VERSION 5.4 ;
NAMESCASESENSITIVE ON ;
BUSBITCHARS "[]" ;
DIVIDERCHAR "/" ;
UNITS
  DATABASE MICRONS 2000 ;
END UNITS
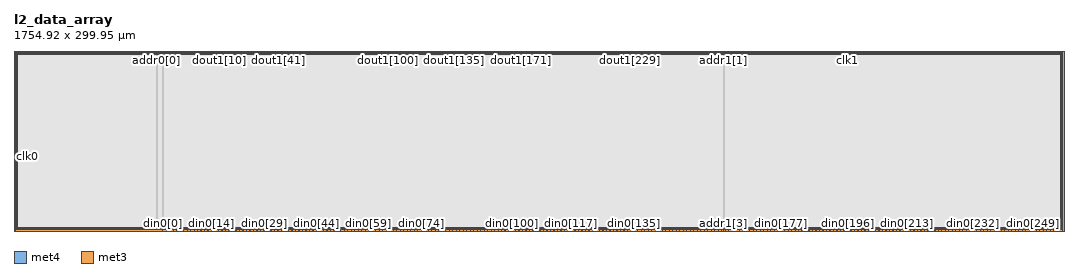
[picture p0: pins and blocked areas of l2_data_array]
MACRO l2_data_array
   CLASS BLOCK ;
   SIZE 1754.92 BY 299.95 ;
   SYMMETRY X Y R90 ;
   PIN din0[0]
      DIRECTION INPUT ;
      PORT
         LAYER met4 ;
         RECT  248.3 0.0 248.68 0.38 ;
      END
   END din0[0]
   PIN din0[1]
      DIRECTION INPUT ;
      PORT
         LAYER met4 ;
         RECT  254.14 0.0 254.52 0.38 ;
      END
   END din0[1]
   PIN din0[2]
      DIRECTION INPUT ;
      PORT
         LAYER met4 ;
         RECT  259.98 0.0 260.36 0.38 ;
      END
   END din0[2]
   PIN din0[3]
      DIRECTION INPUT ;
      PORT
         LAYER met4 ;
         RECT  265.82 0.0 266.2 0.38 ;
      END
   END din0[3]
   PIN din0[4]
      DIRECTION INPUT ;
      PORT
         LAYER met4 ;
         RECT  271.66 0.0 272.04 0.38 ;
      END
   END din0[4]
   PIN din0[5]
      DIRECTION INPUT ;
      PORT
         LAYER met4 ;
         RECT  277.5 0.0 277.88 0.38 ;
      END
   END din0[5]
   PIN din0[6]
      DIRECTION INPUT ;
      PORT
         LAYER met4 ;
         RECT  283.34 0.0 283.72 0.38 ;
      END
   END din0[6]
   PIN din0[7]
      DIRECTION INPUT ;
      PORT
         LAYER met4 ;
         RECT  289.18 0.0 289.56 0.38 ;
      END
   END din0[7]
   PIN din0[8]
      DIRECTION INPUT ;
      PORT
         LAYER met4 ;
         RECT  295.02 0.0 295.4 0.38 ;
      END
   END din0[8]
   PIN din0[9]
      DIRECTION INPUT ;
      PORT
         LAYER met4 ;
         RECT  300.86 0.0 301.24 0.38 ;
      END
   END din0[9]
   PIN din0[10]
      DIRECTION INPUT ;
      PORT
         LAYER met4 ;
         RECT  306.7 0.0 307.08 0.38 ;
      END
   END din0[10]
   PIN din0[11]
      DIRECTION INPUT ;
      PORT
         LAYER met4 ;
         RECT  312.54 0.0 312.92 0.38 ;
      END
   END din0[11]
   PIN din0[12]
      DIRECTION INPUT ;
      PORT
         LAYER met4 ;
         RECT  318.38 0.0 318.76 0.38 ;
      END
   END din0[12]
   PIN din0[13]
      DIRECTION INPUT ;
      PORT
         LAYER met4 ;
         RECT  324.22 0.0 324.6 0.38 ;
      END
   END din0[13]
   PIN din0[14]
      DIRECTION INPUT ;
      PORT
         LAYER met4 ;
         RECT  330.06 0.0 330.44 0.38 ;
      END
   END din0[14]
   PIN din0[15]
      DIRECTION INPUT ;
      PORT
         LAYER met4 ;
         RECT  335.9 0.0 336.28 0.38 ;
      END
   END din0[15]
   PIN din0[16]
      DIRECTION INPUT ;
      PORT
         LAYER met4 ;
         RECT  341.74 0.0 342.12 0.38 ;
      END
   END din0[16]
   PIN din0[17]
      DIRECTION INPUT ;
      PORT
         LAYER met4 ;
         RECT  347.58 0.0 347.96 0.38 ;
      END
   END din0[17]
   PIN din0[18]
      DIRECTION INPUT ;
      PORT
         LAYER met4 ;
         RECT  353.42 0.0 353.8 0.38 ;
      END
   END din0[18]
   PIN din0[19]
      DIRECTION INPUT ;
      PORT
         LAYER met4 ;
         RECT  359.26 0.0 359.64 0.38 ;
      END
   END din0[19]
   PIN din0[20]
      DIRECTION INPUT ;
      PORT
         LAYER met4 ;
         RECT  365.1 0.0 365.48 0.38 ;
      END
   END din0[20]
   PIN din0[21]
      DIRECTION INPUT ;
      PORT
         LAYER met4 ;
         RECT  370.94 0.0 371.32 0.38 ;
      END
   END din0[21]
   PIN din0[22]
      DIRECTION INPUT ;
      PORT
         LAYER met4 ;
         RECT  376.78 0.0 377.16 0.38 ;
      END
   END din0[22]
   PIN din0[23]
      DIRECTION INPUT ;
      PORT
         LAYER met4 ;
         RECT  382.62 0.0 383.0 0.38 ;
      END
   END din0[23]
   PIN din0[24]
      DIRECTION INPUT ;
      PORT
         LAYER met4 ;
         RECT  388.46 0.0 388.84 0.38 ;
      END
   END din0[24]
   PIN din0[25]
      DIRECTION INPUT ;
      PORT
         LAYER met4 ;
         RECT  394.3 0.0 394.68 0.38 ;
      END
   END din0[25]
   PIN din0[26]
      DIRECTION INPUT ;
      PORT
         LAYER met4 ;
         RECT  400.14 0.0 400.52 0.38 ;
      END
   END din0[26]
   PIN din0[27]
      DIRECTION INPUT ;
      PORT
         LAYER met4 ;
         RECT  405.98 0.0 406.36 0.38 ;
      END
   END din0[27]
   PIN din0[28]
      DIRECTION INPUT ;
      PORT
         LAYER met4 ;
         RECT  411.82 0.0 412.2 0.38 ;
      END
   END din0[28]
   PIN din0[29]
      DIRECTION INPUT ;
      PORT
         LAYER met4 ;
         RECT  417.66 0.0 418.04 0.38 ;
      END
   END din0[29]
   PIN din0[30]
      DIRECTION INPUT ;
      PORT
         LAYER met4 ;
         RECT  423.5 0.0 423.88 0.38 ;
      END
   END din0[30]
   PIN din0[31]
      DIRECTION INPUT ;
      PORT
         LAYER met4 ;
         RECT  429.34 0.0 429.72 0.38 ;
      END
   END din0[31]
   PIN din0[32]
      DIRECTION INPUT ;
      PORT
         LAYER met4 ;
         RECT  435.18 0.0 435.56 0.38 ;
      END
   END din0[32]
   PIN din0[33]
      DIRECTION INPUT ;
      PORT
         LAYER met4 ;
         RECT  441.02 0.0 441.4 0.38 ;
      END
   END din0[33]
   PIN din0[34]
      DIRECTION INPUT ;
      PORT
         LAYER met4 ;
         RECT  446.86 0.0 447.24 0.38 ;
      END
   END din0[34]
   PIN din0[35]
      DIRECTION INPUT ;
      PORT
         LAYER met4 ;
         RECT  452.7 0.0 453.08 0.38 ;
      END
   END din0[35]
   PIN din0[36]
      DIRECTION INPUT ;
      PORT
         LAYER met4 ;
         RECT  458.54 0.0 458.92 0.38 ;
      END
   END din0[36]
   PIN din0[37]
      DIRECTION INPUT ;
      PORT
         LAYER met4 ;
         RECT  464.38 0.0 464.76 0.38 ;
      END
   END din0[37]
   PIN din0[38]
      DIRECTION INPUT ;
      PORT
         LAYER met4 ;
         RECT  470.22 0.0 470.6 0.38 ;
      END
   END din0[38]
   PIN din0[39]
      DIRECTION INPUT ;
      PORT
         LAYER met4 ;
         RECT  476.06 0.0 476.44 0.38 ;
      END
   END din0[39]
   PIN din0[40]
      DIRECTION INPUT ;
      PORT
         LAYER met4 ;
         RECT  481.9 0.0 482.28 0.38 ;
      END
   END din0[40]
   PIN din0[41]
      DIRECTION INPUT ;
      PORT
         LAYER met4 ;
         RECT  487.74 0.0 488.12 0.38 ;
      END
   END din0[41]
   PIN din0[42]
      DIRECTION INPUT ;
      PORT
         LAYER met4 ;
         RECT  493.58 0.0 493.96 0.38 ;
      END
   END din0[42]
   PIN din0[43]
      DIRECTION INPUT ;
      PORT
         LAYER met4 ;
         RECT  499.42 0.0 499.8 0.38 ;
      END
   END din0[43]
   PIN din0[44]
      DIRECTION INPUT ;
      PORT
         LAYER met4 ;
         RECT  505.26 0.0 505.64 0.38 ;
      END
   END din0[44]
   PIN din0[45]
      DIRECTION INPUT ;
      PORT
         LAYER met4 ;
         RECT  511.1 0.0 511.48 0.38 ;
      END
   END din0[45]
   PIN din0[46]
      DIRECTION INPUT ;
      PORT
         LAYER met4 ;
         RECT  516.94 0.0 517.32 0.38 ;
      END
   END din0[46]
   PIN din0[47]
      DIRECTION INPUT ;
      PORT
         LAYER met4 ;
         RECT  522.78 0.0 523.16 0.38 ;
      END
   END din0[47]
   PIN din0[48]
      DIRECTION INPUT ;
      PORT
         LAYER met4 ;
         RECT  528.62 0.0 529.0 0.38 ;
      END
   END din0[48]
   PIN din0[49]
      DIRECTION INPUT ;
      PORT
         LAYER met4 ;
         RECT  534.46 0.0 534.84 0.38 ;
      END
   END din0[49]
   PIN din0[50]
      DIRECTION INPUT ;
      PORT
         LAYER met4 ;
         RECT  540.3 0.0 540.68 0.38 ;
      END
   END din0[50]
   PIN din0[51]
      DIRECTION INPUT ;
      PORT
         LAYER met4 ;
         RECT  546.14 0.0 546.52 0.38 ;
      END
   END din0[51]
   PIN din0[52]
      DIRECTION INPUT ;
      PORT
         LAYER met4 ;
         RECT  551.98 0.0 552.36 0.38 ;
      END
   END din0[52]
   PIN din0[53]
      DIRECTION INPUT ;
      PORT
         LAYER met4 ;
         RECT  557.82 0.0 558.2 0.38 ;
      END
   END din0[53]
   PIN din0[54]
      DIRECTION INPUT ;
      PORT
         LAYER met4 ;
         RECT  563.66 0.0 564.04 0.38 ;
      END
   END din0[54]
   PIN din0[55]
      DIRECTION INPUT ;
      PORT
         LAYER met4 ;
         RECT  569.5 0.0 569.88 0.38 ;
      END
   END din0[55]
   PIN din0[56]
      DIRECTION INPUT ;
      PORT
         LAYER met4 ;
         RECT  575.34 0.0 575.72 0.38 ;
      END
   END din0[56]
   PIN din0[57]
      DIRECTION INPUT ;
      PORT
         LAYER met4 ;
         RECT  581.18 0.0 581.56 0.38 ;
      END
   END din0[57]
   PIN din0[58]
      DIRECTION INPUT ;
      PORT
         LAYER met4 ;
         RECT  587.02 0.0 587.4 0.38 ;
      END
   END din0[58]
   PIN din0[59]
      DIRECTION INPUT ;
      PORT
         LAYER met4 ;
         RECT  592.86 0.0 593.24 0.38 ;
      END
   END din0[59]
   PIN din0[60]
      DIRECTION INPUT ;
      PORT
         LAYER met4 ;
         RECT  598.7 0.0 599.08 0.38 ;
      END
   END din0[60]
   PIN din0[61]
      DIRECTION INPUT ;
      PORT
         LAYER met4 ;
         RECT  604.54 0.0 604.92 0.38 ;
      END
   END din0[61]
   PIN din0[62]
      DIRECTION INPUT ;
      PORT
         LAYER met4 ;
         RECT  610.38 0.0 610.76 0.38 ;
      END
   END din0[62]
   PIN din0[63]
      DIRECTION INPUT ;
      PORT
         LAYER met4 ;
         RECT  616.22 0.0 616.6 0.38 ;
      END
   END din0[63]
   PIN din0[64]
      DIRECTION INPUT ;
      PORT
         LAYER met4 ;
         RECT  622.06 0.0 622.44 0.38 ;
      END
   END din0[64]
   PIN din0[65]
      DIRECTION INPUT ;
      PORT
         LAYER met4 ;
         RECT  627.9 0.0 628.28 0.38 ;
      END
   END din0[65]
   PIN din0[66]
      DIRECTION INPUT ;
      PORT
         LAYER met4 ;
         RECT  633.74 0.0 634.12 0.38 ;
      END
   END din0[66]
   PIN din0[67]
      DIRECTION INPUT ;
      PORT
         LAYER met4 ;
         RECT  639.58 0.0 639.96 0.38 ;
      END
   END din0[67]
   PIN din0[68]
      DIRECTION INPUT ;
      PORT
         LAYER met4 ;
         RECT  645.42 0.0 645.8 0.38 ;
      END
   END din0[68]
   PIN din0[69]
      DIRECTION INPUT ;
      PORT
         LAYER met4 ;
         RECT  651.26 0.0 651.64 0.38 ;
      END
   END din0[69]
   PIN din0[70]
      DIRECTION INPUT ;
      PORT
         LAYER met4 ;
         RECT  657.1 0.0 657.48 0.38 ;
      END
   END din0[70]
   PIN din0[71]
      DIRECTION INPUT ;
      PORT
         LAYER met4 ;
         RECT  662.94 0.0 663.32 0.38 ;
      END
   END din0[71]
   PIN din0[72]
      DIRECTION INPUT ;
      PORT
         LAYER met4 ;
         RECT  668.78 0.0 669.16 0.38 ;
      END
   END din0[72]
   PIN din0[73]
      DIRECTION INPUT ;
      PORT
         LAYER met4 ;
         RECT  674.62 0.0 675.0 0.38 ;
      END
   END din0[73]
   PIN din0[74]
      DIRECTION INPUT ;
      PORT
         LAYER met4 ;
         RECT  680.46 0.0 680.84 0.38 ;
      END
   END din0[74]
   PIN din0[75]
      DIRECTION INPUT ;
      PORT
         LAYER met4 ;
         RECT  686.3 0.0 686.68 0.38 ;
      END
   END din0[75]
   PIN din0[76]
      DIRECTION INPUT ;
      PORT
         LAYER met4 ;
         RECT  692.14 0.0 692.52 0.38 ;
      END
   END din0[76]
   PIN din0[77]
      DIRECTION INPUT ;
      PORT
         LAYER met4 ;
         RECT  697.98 0.0 698.36 0.38 ;
      END
   END din0[77]
   PIN din0[78]
      DIRECTION INPUT ;
      PORT
         LAYER met4 ;
         RECT  703.82 0.0 704.2 0.38 ;
      END
   END din0[78]
   PIN din0[79]
      DIRECTION INPUT ;
      PORT
         LAYER met4 ;
         RECT  709.66 0.0 710.04 0.38 ;
      END
   END din0[79]
   PIN din0[80]
      DIRECTION INPUT ;
      PORT
         LAYER met4 ;
         RECT  715.5 0.0 715.88 0.38 ;
      END
   END din0[80]
   PIN din0[81]
      DIRECTION INPUT ;
      PORT
         LAYER met4 ;
         RECT  721.34 0.0 721.72 0.38 ;
      END
   END din0[81]
   PIN din0[82]
      DIRECTION INPUT ;
      PORT
         LAYER met4 ;
         RECT  727.18 0.0 727.56 0.38 ;
      END
   END din0[82]
   PIN din0[83]
      DIRECTION INPUT ;
      PORT
         LAYER met4 ;
         RECT  733.02 0.0 733.4 0.38 ;
      END
   END din0[83]
   PIN din0[84]
      DIRECTION INPUT ;
      PORT
         LAYER met4 ;
         RECT  738.86 0.0 739.24 0.38 ;
      END
   END din0[84]
   PIN din0[85]
      DIRECTION INPUT ;
      PORT
         LAYER met4 ;
         RECT  744.7 0.0 745.08 0.38 ;
      END
   END din0[85]
   PIN din0[86]
      DIRECTION INPUT ;
      PORT
         LAYER met4 ;
         RECT  750.54 0.0 750.92 0.38 ;
      END
   END din0[86]
   PIN din0[87]
      DIRECTION INPUT ;
      PORT
         LAYER met4 ;
         RECT  756.38 0.0 756.76 0.38 ;
      END
   END din0[87]
   PIN din0[88]
      DIRECTION INPUT ;
      PORT
         LAYER met4 ;
         RECT  762.22 0.0 762.6 0.38 ;
      END
   END din0[88]
   PIN din0[89]
      DIRECTION INPUT ;
      PORT
         LAYER met4 ;
         RECT  768.06 0.0 768.44 0.38 ;
      END
   END din0[89]
   PIN din0[90]
      DIRECTION INPUT ;
      PORT
         LAYER met4 ;
         RECT  773.9 0.0 774.28 0.38 ;
      END
   END din0[90]
   PIN din0[91]
      DIRECTION INPUT ;
      PORT
         LAYER met4 ;
         RECT  779.74 0.0 780.12 0.38 ;
      END
   END din0[91]
   PIN din0[92]
      DIRECTION INPUT ;
      PORT
         LAYER met4 ;
         RECT  785.58 0.0 785.96 0.38 ;
      END
   END din0[92]
   PIN din0[93]
      DIRECTION INPUT ;
      PORT
         LAYER met4 ;
         RECT  791.42 0.0 791.8 0.38 ;
      END
   END din0[93]
   PIN din0[94]
      DIRECTION INPUT ;
      PORT
         LAYER met4 ;
         RECT  797.26 0.0 797.64 0.38 ;
      END
   END din0[94]
   PIN din0[95]
      DIRECTION INPUT ;
      PORT
         LAYER met4 ;
         RECT  803.1 0.0 803.48 0.38 ;
      END
   END din0[95]
   PIN din0[96]
      DIRECTION INPUT ;
      PORT
         LAYER met4 ;
         RECT  808.94 0.0 809.32 0.38 ;
      END
   END din0[96]
   PIN din0[97]
      DIRECTION INPUT ;
      PORT
         LAYER met4 ;
         RECT  814.78 0.0 815.16 0.38 ;
      END
   END din0[97]
   PIN din0[98]
      DIRECTION INPUT ;
      PORT
         LAYER met4 ;
         RECT  820.62 0.0 821.0 0.38 ;
      END
   END din0[98]
   PIN din0[99]
      DIRECTION INPUT ;
      PORT
         LAYER met4 ;
         RECT  826.46 0.0 826.84 0.38 ;
      END
   END din0[99]
   PIN din0[100]
      DIRECTION INPUT ;
      PORT
         LAYER met4 ;
         RECT  832.3 0.0 832.68 0.38 ;
      END
   END din0[100]
   PIN din0[101]
      DIRECTION INPUT ;
      PORT
         LAYER met4 ;
         RECT  838.14 0.0 838.52 0.38 ;
      END
   END din0[101]
   PIN din0[102]
      DIRECTION INPUT ;
      PORT
         LAYER met4 ;
         RECT  843.98 0.0 844.36 0.38 ;
      END
   END din0[102]
   PIN din0[103]
      DIRECTION INPUT ;
      PORT
         LAYER met4 ;
         RECT  849.82 0.0 850.2 0.38 ;
      END
   END din0[103]
   PIN din0[104]
      DIRECTION INPUT ;
      PORT
         LAYER met4 ;
         RECT  855.66 0.0 856.04 0.38 ;
      END
   END din0[104]
   PIN din0[105]
      DIRECTION INPUT ;
      PORT
         LAYER met4 ;
         RECT  861.5 0.0 861.88 0.38 ;
      END
   END din0[105]
   PIN din0[106]
      DIRECTION INPUT ;
      PORT
         LAYER met4 ;
         RECT  867.34 0.0 867.72 0.38 ;
      END
   END din0[106]
   PIN din0[107]
      DIRECTION INPUT ;
      PORT
         LAYER met4 ;
         RECT  873.18 0.0 873.56 0.38 ;
      END
   END din0[107]
   PIN din0[108]
      DIRECTION INPUT ;
      PORT
         LAYER met4 ;
         RECT  879.02 0.0 879.4 0.38 ;
      END
   END din0[108]
   PIN din0[109]
      DIRECTION INPUT ;
      PORT
         LAYER met4 ;
         RECT  884.86 0.0 885.24 0.38 ;
      END
   END din0[109]
   PIN din0[110]
      DIRECTION INPUT ;
      PORT
         LAYER met4 ;
         RECT  890.7 0.0 891.08 0.38 ;
      END
   END din0[110]
   PIN din0[111]
      DIRECTION INPUT ;
      PORT
         LAYER met4 ;
         RECT  896.54 0.0 896.92 0.38 ;
      END
   END din0[111]
   PIN din0[112]
      DIRECTION INPUT ;
      PORT
         LAYER met4 ;
         RECT  902.38 0.0 902.76 0.38 ;
      END
   END din0[112]
   PIN din0[113]
      DIRECTION INPUT ;
      PORT
         LAYER met4 ;
         RECT  908.22 0.0 908.6 0.38 ;
      END
   END din0[113]
   PIN din0[114]
      DIRECTION INPUT ;
      PORT
         LAYER met4 ;
         RECT  914.06 0.0 914.44 0.38 ;
      END
   END din0[114]
   PIN din0[115]
      DIRECTION INPUT ;
      PORT
         LAYER met4 ;
         RECT  919.9 0.0 920.28 0.38 ;
      END
   END din0[115]
   PIN din0[116]
      DIRECTION INPUT ;
      PORT
         LAYER met4 ;
         RECT  925.74 0.0 926.12 0.38 ;
      END
   END din0[116]
   PIN din0[117]
      DIRECTION INPUT ;
      PORT
         LAYER met4 ;
         RECT  931.58 0.0 931.96 0.38 ;
      END
   END din0[117]
   PIN din0[118]
      DIRECTION INPUT ;
      PORT
         LAYER met4 ;
         RECT  937.42 0.0 937.8 0.38 ;
      END
   END din0[118]
   PIN din0[119]
      DIRECTION INPUT ;
      PORT
         LAYER met4 ;
         RECT  943.26 0.0 943.64 0.38 ;
      END
   END din0[119]
   PIN din0[120]
      DIRECTION INPUT ;
      PORT
         LAYER met4 ;
         RECT  949.1 0.0 949.48 0.38 ;
      END
   END din0[120]
   PIN din0[121]
      DIRECTION INPUT ;
      PORT
         LAYER met4 ;
         RECT  954.94 0.0 955.32 0.38 ;
      END
   END din0[121]
   PIN din0[122]
      DIRECTION INPUT ;
      PORT
         LAYER met4 ;
         RECT  960.78 0.0 961.16 0.38 ;
      END
   END din0[122]
   PIN din0[123]
      DIRECTION INPUT ;
      PORT
         LAYER met4 ;
         RECT  966.62 0.0 967.0 0.38 ;
      END
   END din0[123]
   PIN din0[124]
      DIRECTION INPUT ;
      PORT
         LAYER met4 ;
         RECT  972.46 0.0 972.84 0.38 ;
      END
   END din0[124]
   PIN din0[125]
      DIRECTION INPUT ;
      PORT
         LAYER met4 ;
         RECT  978.3 0.0 978.68 0.38 ;
      END
   END din0[125]
   PIN din0[126]
      DIRECTION INPUT ;
      PORT
         LAYER met4 ;
         RECT  984.14 0.0 984.52 0.38 ;
      END
   END din0[126]
   PIN din0[127]
      DIRECTION INPUT ;
      PORT
         LAYER met4 ;
         RECT  989.98 0.0 990.36 0.38 ;
      END
   END din0[127]
   PIN din0[128]
      DIRECTION INPUT ;
      PORT
         LAYER met4 ;
         RECT  995.82 0.0 996.2 0.38 ;
      END
   END din0[128]
   PIN din0[129]
      DIRECTION INPUT ;
      PORT
         LAYER met4 ;
         RECT  1001.66 0.0 1002.04 0.38 ;
      END
   END din0[129]
   PIN din0[130]
      DIRECTION INPUT ;
      PORT
         LAYER met4 ;
         RECT  1007.5 0.0 1007.88 0.38 ;
      END
   END din0[130]
   PIN din0[131]
      DIRECTION INPUT ;
      PORT
         LAYER met4 ;
         RECT  1013.34 0.0 1013.72 0.38 ;
      END
   END din0[131]
   PIN din0[132]
      DIRECTION INPUT ;
      PORT
         LAYER met4 ;
         RECT  1019.18 0.0 1019.56 0.38 ;
      END
   END din0[132]
   PIN din0[133]
      DIRECTION INPUT ;
      PORT
         LAYER met4 ;
         RECT  1025.02 0.0 1025.4 0.38 ;
      END
   END din0[133]
   PIN din0[134]
      DIRECTION INPUT ;
      PORT
         LAYER met4 ;
         RECT  1030.86 0.0 1031.24 0.38 ;
      END
   END din0[134]
   PIN din0[135]
      DIRECTION INPUT ;
      PORT
         LAYER met4 ;
         RECT  1036.7 0.0 1037.08 0.38 ;
      END
   END din0[135]
   PIN din0[136]
      DIRECTION INPUT ;
      PORT
         LAYER met4 ;
         RECT  1042.54 0.0 1042.92 0.38 ;
      END
   END din0[136]
   PIN din0[137]
      DIRECTION INPUT ;
      PORT
         LAYER met4 ;
         RECT  1048.38 0.0 1048.76 0.38 ;
      END
   END din0[137]
   PIN din0[138]
      DIRECTION INPUT ;
      PORT
         LAYER met4 ;
         RECT  1054.22 0.0 1054.6 0.38 ;
      END
   END din0[138]
   PIN din0[139]
      DIRECTION INPUT ;
      PORT
         LAYER met4 ;
         RECT  1060.06 0.0 1060.44 0.38 ;
      END
   END din0[139]
   PIN din0[140]
      DIRECTION INPUT ;
      PORT
         LAYER met4 ;
         RECT  1065.9 0.0 1066.28 0.38 ;
      END
   END din0[140]
   PIN din0[141]
      DIRECTION INPUT ;
      PORT
         LAYER met4 ;
         RECT  1071.74 0.0 1072.12 0.38 ;
      END
   END din0[141]
   PIN din0[142]
      DIRECTION INPUT ;
      PORT
         LAYER met4 ;
         RECT  1077.58 0.0 1077.96 0.38 ;
      END
   END din0[142]
   PIN din0[143]
      DIRECTION INPUT ;
      PORT
         LAYER met4 ;
         RECT  1083.42 0.0 1083.8 0.38 ;
      END
   END din0[143]
   PIN din0[144]
      DIRECTION INPUT ;
      PORT
         LAYER met4 ;
         RECT  1089.26 0.0 1089.64 0.38 ;
      END
   END din0[144]
   PIN din0[145]
      DIRECTION INPUT ;
      PORT
         LAYER met4 ;
         RECT  1095.1 0.0 1095.48 0.38 ;
      END
   END din0[145]
   PIN din0[146]
      DIRECTION INPUT ;
      PORT
         LAYER met4 ;
         RECT  1100.94 0.0 1101.32 0.38 ;
      END
   END din0[146]
   PIN din0[147]
      DIRECTION INPUT ;
      PORT
         LAYER met4 ;
         RECT  1106.78 0.0 1107.16 0.38 ;
      END
   END din0[147]
   PIN din0[148]
      DIRECTION INPUT ;
      PORT
         LAYER met4 ;
         RECT  1112.62 0.0 1113.0 0.38 ;
      END
   END din0[148]
   PIN din0[149]
      DIRECTION INPUT ;
      PORT
         LAYER met4 ;
         RECT  1118.46 0.0 1118.84 0.38 ;
      END
   END din0[149]
   PIN din0[150]
      DIRECTION INPUT ;
      PORT
         LAYER met4 ;
         RECT  1124.3 0.0 1124.68 0.38 ;
      END
   END din0[150]
   PIN din0[151]
      DIRECTION INPUT ;
      PORT
         LAYER met4 ;
         RECT  1130.14 0.0 1130.52 0.38 ;
      END
   END din0[151]
   PIN din0[152]
      DIRECTION INPUT ;
      PORT
         LAYER met4 ;
         RECT  1135.98 0.0 1136.36 0.38 ;
      END
   END din0[152]
   PIN din0[153]
      DIRECTION INPUT ;
      PORT
         LAYER met4 ;
         RECT  1141.82 0.0 1142.2 0.38 ;
      END
   END din0[153]
   PIN din0[154]
      DIRECTION INPUT ;
      PORT
         LAYER met4 ;
         RECT  1147.66 0.0 1148.04 0.38 ;
      END
   END din0[154]
   PIN din0[155]
      DIRECTION INPUT ;
      PORT
         LAYER met4 ;
         RECT  1153.5 0.0 1153.88 0.38 ;
      END
   END din0[155]
   PIN din0[156]
      DIRECTION INPUT ;
      PORT
         LAYER met4 ;
         RECT  1159.34 0.0 1159.72 0.38 ;
      END
   END din0[156]
   PIN din0[157]
      DIRECTION INPUT ;
      PORT
         LAYER met4 ;
         RECT  1165.18 0.0 1165.56 0.38 ;
      END
   END din0[157]
   PIN din0[158]
      DIRECTION INPUT ;
      PORT
         LAYER met4 ;
         RECT  1171.02 0.0 1171.4 0.38 ;
      END
   END din0[158]
   PIN din0[159]
      DIRECTION INPUT ;
      PORT
         LAYER met4 ;
         RECT  1176.86 0.0 1177.24 0.38 ;
      END
   END din0[159]
   PIN din0[160]
      DIRECTION INPUT ;
      PORT
         LAYER met4 ;
         RECT  1182.7 0.0 1183.08 0.38 ;
      END
   END din0[160]
   PIN din0[161]
      DIRECTION INPUT ;
      PORT
         LAYER met4 ;
         RECT  1188.54 0.0 1188.92 0.38 ;
      END
   END din0[161]
   PIN din0[162]
      DIRECTION INPUT ;
      PORT
         LAYER met4 ;
         RECT  1194.38 0.0 1194.76 0.38 ;
      END
   END din0[162]
   PIN din0[163]
      DIRECTION INPUT ;
      PORT
         LAYER met4 ;
         RECT  1200.22 0.0 1200.6 0.38 ;
      END
   END din0[163]
   PIN din0[164]
      DIRECTION INPUT ;
      PORT
         LAYER met4 ;
         RECT  1206.06 0.0 1206.44 0.38 ;
      END
   END din0[164]
   PIN din0[165]
      DIRECTION INPUT ;
      PORT
         LAYER met4 ;
         RECT  1211.9 0.0 1212.28 0.38 ;
      END
   END din0[165]
   PIN din0[166]
      DIRECTION INPUT ;
      PORT
         LAYER met4 ;
         RECT  1217.74 0.0 1218.12 0.38 ;
      END
   END din0[166]
   PIN din0[167]
      DIRECTION INPUT ;
      PORT
         LAYER met4 ;
         RECT  1223.58 0.0 1223.96 0.38 ;
      END
   END din0[167]
   PIN din0[168]
      DIRECTION INPUT ;
      PORT
         LAYER met4 ;
         RECT  1229.42 0.0 1229.8 0.38 ;
      END
   END din0[168]
   PIN din0[169]
      DIRECTION INPUT ;
      PORT
         LAYER met4 ;
         RECT  1235.26 0.0 1235.64 0.38 ;
      END
   END din0[169]
   PIN din0[170]
      DIRECTION INPUT ;
      PORT
         LAYER met4 ;
         RECT  1241.1 0.0 1241.48 0.38 ;
      END
   END din0[170]
   PIN din0[171]
      DIRECTION INPUT ;
      PORT
         LAYER met4 ;
         RECT  1246.94 0.0 1247.32 0.38 ;
      END
   END din0[171]
   PIN din0[172]
      DIRECTION INPUT ;
      PORT
         LAYER met4 ;
         RECT  1252.78 0.0 1253.16 0.38 ;
      END
   END din0[172]
   PIN din0[173]
      DIRECTION INPUT ;
      PORT
         LAYER met4 ;
         RECT  1258.62 0.0 1259.0 0.38 ;
      END
   END din0[173]
   PIN din0[174]
      DIRECTION INPUT ;
      PORT
         LAYER met4 ;
         RECT  1264.46 0.0 1264.84 0.38 ;
      END
   END din0[174]
   PIN din0[175]
      DIRECTION INPUT ;
      PORT
         LAYER met4 ;
         RECT  1270.3 0.0 1270.68 0.38 ;
      END
   END din0[175]
   PIN din0[176]
      DIRECTION INPUT ;
      PORT
         LAYER met4 ;
         RECT  1276.14 0.0 1276.52 0.38 ;
      END
   END din0[176]
   PIN din0[177]
      DIRECTION INPUT ;
      PORT
         LAYER met4 ;
         RECT  1281.98 0.0 1282.36 0.38 ;
      END
   END din0[177]
   PIN din0[178]
      DIRECTION INPUT ;
      PORT
         LAYER met4 ;
         RECT  1287.82 0.0 1288.2 0.38 ;
      END
   END din0[178]
   PIN din0[179]
      DIRECTION INPUT ;
      PORT
         LAYER met4 ;
         RECT  1293.66 0.0 1294.04 0.38 ;
      END
   END din0[179]
   PIN din0[180]
      DIRECTION INPUT ;
      PORT
         LAYER met4 ;
         RECT  1299.5 0.0 1299.88 0.38 ;
      END
   END din0[180]
   PIN din0[181]
      DIRECTION INPUT ;
      PORT
         LAYER met4 ;
         RECT  1305.34 0.0 1305.72 0.38 ;
      END
   END din0[181]
   PIN din0[182]
      DIRECTION INPUT ;
      PORT
         LAYER met4 ;
         RECT  1311.18 0.0 1311.56 0.38 ;
      END
   END din0[182]
   PIN din0[183]
      DIRECTION INPUT ;
      PORT
         LAYER met4 ;
         RECT  1317.02 0.0 1317.4 0.38 ;
      END
   END din0[183]
   PIN din0[184]
      DIRECTION INPUT ;
      PORT
         LAYER met4 ;
         RECT  1322.86 0.0 1323.24 0.38 ;
      END
   END din0[184]
   PIN din0[185]
      DIRECTION INPUT ;
      PORT
         LAYER met4 ;
         RECT  1328.7 0.0 1329.08 0.38 ;
      END
   END din0[185]
   PIN din0[186]
      DIRECTION INPUT ;
      PORT
         LAYER met4 ;
         RECT  1334.54 0.0 1334.92 0.38 ;
      END
   END din0[186]
   PIN din0[187]
      DIRECTION INPUT ;
      PORT
         LAYER met4 ;
         RECT  1340.38 0.0 1340.76 0.38 ;
      END
   END din0[187]
   PIN din0[188]
      DIRECTION INPUT ;
      PORT
         LAYER met4 ;
         RECT  1346.22 0.0 1346.6 0.38 ;
      END
   END din0[188]
   PIN din0[189]
      DIRECTION INPUT ;
      PORT
         LAYER met4 ;
         RECT  1352.06 0.0 1352.44 0.38 ;
      END
   END din0[189]
   PIN din0[190]
      DIRECTION INPUT ;
      PORT
         LAYER met4 ;
         RECT  1357.9 0.0 1358.28 0.38 ;
      END
   END din0[190]
   PIN din0[191]
      DIRECTION INPUT ;
      PORT
         LAYER met4 ;
         RECT  1363.74 0.0 1364.12 0.38 ;
      END
   END din0[191]
   PIN din0[192]
      DIRECTION INPUT ;
      PORT
         LAYER met4 ;
         RECT  1369.58 0.0 1369.96 0.38 ;
      END
   END din0[192]
   PIN din0[193]
      DIRECTION INPUT ;
      PORT
         LAYER met4 ;
         RECT  1375.42 0.0 1375.8 0.38 ;
      END
   END din0[193]
   PIN din0[194]
      DIRECTION INPUT ;
      PORT
         LAYER met4 ;
         RECT  1381.26 0.0 1381.64 0.38 ;
      END
   END din0[194]
   PIN din0[195]
      DIRECTION INPUT ;
      PORT
         LAYER met4 ;
         RECT  1387.1 0.0 1387.48 0.38 ;
      END
   END din0[195]
   PIN din0[196]
      DIRECTION INPUT ;
      PORT
         LAYER met4 ;
         RECT  1392.94 0.0 1393.32 0.38 ;
      END
   END din0[196]
   PIN din0[197]
      DIRECTION INPUT ;
      PORT
         LAYER met4 ;
         RECT  1398.78 0.0 1399.16 0.38 ;
      END
   END din0[197]
   PIN din0[198]
      DIRECTION INPUT ;
      PORT
         LAYER met4 ;
         RECT  1404.62 0.0 1405.0 0.38 ;
      END
   END din0[198]
   PIN din0[199]
      DIRECTION INPUT ;
      PORT
         LAYER met4 ;
         RECT  1410.46 0.0 1410.84 0.38 ;
      END
   END din0[199]
   PIN din0[200]
      DIRECTION INPUT ;
      PORT
         LAYER met4 ;
         RECT  1416.3 0.0 1416.68 0.38 ;
      END
   END din0[200]
   PIN din0[201]
      DIRECTION INPUT ;
      PORT
         LAYER met4 ;
         RECT  1422.14 0.0 1422.52 0.38 ;
      END
   END din0[201]
   PIN din0[202]
      DIRECTION INPUT ;
      PORT
         LAYER met4 ;
         RECT  1427.98 0.0 1428.36 0.38 ;
      END
   END din0[202]
   PIN din0[203]
      DIRECTION INPUT ;
      PORT
         LAYER met4 ;
         RECT  1433.82 0.0 1434.2 0.38 ;
      END
   END din0[203]
   PIN din0[204]
      DIRECTION INPUT ;
      PORT
         LAYER met4 ;
         RECT  1439.66 0.0 1440.04 0.38 ;
      END
   END din0[204]
   PIN din0[205]
      DIRECTION INPUT ;
      PORT
         LAYER met4 ;
         RECT  1445.5 0.0 1445.88 0.38 ;
      END
   END din0[205]
   PIN din0[206]
      DIRECTION INPUT ;
      PORT
         LAYER met4 ;
         RECT  1451.34 0.0 1451.72 0.38 ;
      END
   END din0[206]
   PIN din0[207]
      DIRECTION INPUT ;
      PORT
         LAYER met4 ;
         RECT  1457.18 0.0 1457.56 0.38 ;
      END
   END din0[207]
   PIN din0[208]
      DIRECTION INPUT ;
      PORT
         LAYER met4 ;
         RECT  1463.02 0.0 1463.4 0.38 ;
      END
   END din0[208]
   PIN din0[209]
      DIRECTION INPUT ;
      PORT
         LAYER met4 ;
         RECT  1468.86 0.0 1469.24 0.38 ;
      END
   END din0[209]
   PIN din0[210]
      DIRECTION INPUT ;
      PORT
         LAYER met4 ;
         RECT  1474.7 0.0 1475.08 0.38 ;
      END
   END din0[210]
   PIN din0[211]
      DIRECTION INPUT ;
      PORT
         LAYER met4 ;
         RECT  1480.54 0.0 1480.92 0.38 ;
      END
   END din0[211]
   PIN din0[212]
      DIRECTION INPUT ;
      PORT
         LAYER met4 ;
         RECT  1486.38 0.0 1486.76 0.38 ;
      END
   END din0[212]
   PIN din0[213]
      DIRECTION INPUT ;
      PORT
         LAYER met4 ;
         RECT  1492.22 0.0 1492.6 0.38 ;
      END
   END din0[213]
   PIN din0[214]
      DIRECTION INPUT ;
      PORT
         LAYER met4 ;
         RECT  1498.06 0.0 1498.44 0.38 ;
      END
   END din0[214]
   PIN din0[215]
      DIRECTION INPUT ;
      PORT
         LAYER met4 ;
         RECT  1503.9 0.0 1504.28 0.38 ;
      END
   END din0[215]
   PIN din0[216]
      DIRECTION INPUT ;
      PORT
         LAYER met4 ;
         RECT  1509.74 0.0 1510.12 0.38 ;
      END
   END din0[216]
   PIN din0[217]
      DIRECTION INPUT ;
      PORT
         LAYER met4 ;
         RECT  1515.58 0.0 1515.96 0.38 ;
      END
   END din0[217]
   PIN din0[218]
      DIRECTION INPUT ;
      PORT
         LAYER met4 ;
         RECT  1521.42 0.0 1521.8 0.38 ;
      END
   END din0[218]
   PIN din0[219]
      DIRECTION INPUT ;
      PORT
         LAYER met4 ;
         RECT  1527.26 0.0 1527.64 0.38 ;
      END
   END din0[219]
   PIN din0[220]
      DIRECTION INPUT ;
      PORT
         LAYER met4 ;
         RECT  1533.1 0.0 1533.48 0.38 ;
      END
   END din0[220]
   PIN din0[221]
      DIRECTION INPUT ;
      PORT
         LAYER met4 ;
         RECT  1538.94 0.0 1539.32 0.38 ;
      END
   END din0[221]
   PIN din0[222]
      DIRECTION INPUT ;
      PORT
         LAYER met4 ;
         RECT  1544.78 0.0 1545.16 0.38 ;
      END
   END din0[222]
   PIN din0[223]
      DIRECTION INPUT ;
      PORT
         LAYER met4 ;
         RECT  1550.62 0.0 1551.0 0.38 ;
      END
   END din0[223]
   PIN din0[224]
      DIRECTION INPUT ;
      PORT
         LAYER met4 ;
         RECT  1556.46 0.0 1556.84 0.38 ;
      END
   END din0[224]
   PIN din0[225]
      DIRECTION INPUT ;
      PORT
         LAYER met4 ;
         RECT  1562.3 0.0 1562.68 0.38 ;
      END
   END din0[225]
   PIN din0[226]
      DIRECTION INPUT ;
      PORT
         LAYER met4 ;
         RECT  1568.14 0.0 1568.52 0.38 ;
      END
   END din0[226]
   PIN din0[227]
      DIRECTION INPUT ;
      PORT
         LAYER met4 ;
         RECT  1573.98 0.0 1574.36 0.38 ;
      END
   END din0[227]
   PIN din0[228]
      DIRECTION INPUT ;
      PORT
         LAYER met4 ;
         RECT  1579.82 0.0 1580.2 0.38 ;
      END
   END din0[228]
   PIN din0[229]
      DIRECTION INPUT ;
      PORT
         LAYER met4 ;
         RECT  1585.66 0.0 1586.04 0.38 ;
      END
   END din0[229]
   PIN din0[230]
      DIRECTION INPUT ;
      PORT
         LAYER met4 ;
         RECT  1591.5 0.0 1591.88 0.38 ;
      END
   END din0[230]
   PIN din0[231]
      DIRECTION INPUT ;
      PORT
         LAYER met4 ;
         RECT  1597.34 0.0 1597.72 0.38 ;
      END
   END din0[231]
   PIN din0[232]
      DIRECTION INPUT ;
      PORT
         LAYER met4 ;
         RECT  1603.18 0.0 1603.56 0.38 ;
      END
   END din0[232]
   PIN din0[233]
      DIRECTION INPUT ;
      PORT
         LAYER met4 ;
         RECT  1609.02 0.0 1609.4 0.38 ;
      END
   END din0[233]
   PIN din0[234]
      DIRECTION INPUT ;
      PORT
         LAYER met4 ;
         RECT  1614.86 0.0 1615.24 0.38 ;
      END
   END din0[234]
   PIN din0[235]
      DIRECTION INPUT ;
      PORT
         LAYER met4 ;
         RECT  1620.7 0.0 1621.08 0.38 ;
      END
   END din0[235]
   PIN din0[236]
      DIRECTION INPUT ;
      PORT
         LAYER met4 ;
         RECT  1626.54 0.0 1626.92 0.38 ;
      END
   END din0[236]
   PIN din0[237]
      DIRECTION INPUT ;
      PORT
         LAYER met4 ;
         RECT  1632.38 0.0 1632.76 0.38 ;
      END
   END din0[237]
   PIN din0[238]
      DIRECTION INPUT ;
      PORT
         LAYER met4 ;
         RECT  1638.22 0.0 1638.6 0.38 ;
      END
   END din0[238]
   PIN din0[239]
      DIRECTION INPUT ;
      PORT
         LAYER met4 ;
         RECT  1644.06 0.0 1644.44 0.38 ;
      END
   END din0[239]
   PIN din0[240]
      DIRECTION INPUT ;
      PORT
         LAYER met4 ;
         RECT  1649.9 0.0 1650.28 0.38 ;
      END
   END din0[240]
   PIN din0[241]
      DIRECTION INPUT ;
      PORT
         LAYER met4 ;
         RECT  1655.74 0.0 1656.12 0.38 ;
      END
   END din0[241]
   PIN din0[242]
      DIRECTION INPUT ;
      PORT
         LAYER met4 ;
         RECT  1661.58 0.0 1661.96 0.38 ;
      END
   END din0[242]
   PIN din0[243]
      DIRECTION INPUT ;
      PORT
         LAYER met4 ;
         RECT  1667.42 0.0 1667.8 0.38 ;
      END
   END din0[243]
   PIN din0[244]
      DIRECTION INPUT ;
      PORT
         LAYER met4 ;
         RECT  1673.26 0.0 1673.64 0.38 ;
      END
   END din0[244]
   PIN din0[245]
      DIRECTION INPUT ;
      PORT
         LAYER met4 ;
         RECT  1679.1 0.0 1679.48 0.38 ;
      END
   END din0[245]
   PIN din0[246]
      DIRECTION INPUT ;
      PORT
         LAYER met4 ;
         RECT  1684.94 0.0 1685.32 0.38 ;
      END
   END din0[246]
   PIN din0[247]
      DIRECTION INPUT ;
      PORT
         LAYER met4 ;
         RECT  1690.78 0.0 1691.16 0.38 ;
      END
   END din0[247]
   PIN din0[248]
      DIRECTION INPUT ;
      PORT
         LAYER met4 ;
         RECT  1696.62 0.0 1697.0 0.38 ;
      END
   END din0[248]
   PIN din0[249]
      DIRECTION INPUT ;
      PORT
         LAYER met4 ;
         RECT  1702.46 0.0 1702.84 0.38 ;
      END
   END din0[249]
   PIN din0[250]
      DIRECTION INPUT ;
      PORT
         LAYER met4 ;
         RECT  1708.3 0.0 1708.68 0.38 ;
      END
   END din0[250]
   PIN din0[251]
      DIRECTION INPUT ;
      PORT
         LAYER met4 ;
         RECT  1714.14 0.0 1714.52 0.38 ;
      END
   END din0[251]
   PIN din0[252]
      DIRECTION INPUT ;
      PORT
         LAYER met4 ;
         RECT  1719.98 0.0 1720.36 0.38 ;
      END
   END din0[252]
   PIN din0[253]
      DIRECTION INPUT ;
      PORT
         LAYER met4 ;
         RECT  1725.82 0.0 1726.2 0.38 ;
      END
   END din0[253]
   PIN din0[254]
      DIRECTION INPUT ;
      PORT
         LAYER met4 ;
         RECT  1731.66 0.0 1732.04 0.38 ;
      END
   END din0[254]
   PIN din0[255]
      DIRECTION INPUT ;
      PORT
         LAYER met4 ;
         RECT  1737.5 0.0 1737.88 0.38 ;
      END
   END din0[255]
   PIN addr0[0]
      DIRECTION INPUT ;
      PORT
         LAYER met4 ;
         RECT  238.745 299.57 239.125 299.95 ;
      END
   END addr0[0]
   PIN addr0[1]
      DIRECTION INPUT ;
      PORT
         LAYER met4 ;
         RECT  235.08 299.57 235.46 299.95 ;
      END
   END addr0[1]
   PIN addr0[2]
      DIRECTION INPUT ;
      PORT
         LAYER met4 ;
         RECT  238.055 299.57 238.435 299.95 ;
      END
   END addr0[2]
   PIN addr0[3]
      DIRECTION INPUT ;
      PORT
         LAYER met4 ;
         RECT  237.365 299.57 237.745 299.95 ;
      END
   END addr0[3]
   PIN addr0[4]
      DIRECTION INPUT ;
      PORT
         LAYER met4 ;
         RECT  236.62 299.57 237.0 299.95 ;
      END
   END addr0[4]
   PIN addr1[0]
      DIRECTION INPUT ;
      PORT
         LAYER met4 ;
         RECT  1185.82 299.57 1186.2 299.95 ;
      END
   END addr1[0]
   PIN addr1[1]
      DIRECTION INPUT ;
      PORT
         LAYER met4 ;
         RECT  1185.075 299.57 1185.455 299.95 ;
      END
   END addr1[1]
   PIN addr1[2]
      DIRECTION INPUT ;
      PORT
         LAYER met4 ;
         RECT  1184.385 299.57 1184.765 299.95 ;
      END
   END addr1[2]
   PIN addr1[3]
      DIRECTION INPUT ;
      PORT
         LAYER met4 ;
         RECT  1185.13 0.0 1185.51 0.38 ;
      END
   END addr1[3]
   PIN addr1[4]
      DIRECTION INPUT ;
      PORT
         LAYER met4 ;
         RECT  1185.82 0.0 1186.2 0.38 ;
      END
   END addr1[4]
   PIN csb0
      DIRECTION INPUT ;
      PORT
         LAYER met3 ;
         RECT  0.0 123.435 0.38 123.815 ;
      END
   END csb0
   PIN csb1
      DIRECTION INPUT ;
      PORT
         LAYER met4 ;
         RECT  1408.95 299.57 1409.33 299.95 ;
      END
   END csb1
   PIN clk0
      DIRECTION INPUT ;
      PORT
         LAYER met3 ;
         RECT  0.0 124.18 0.38 124.56 ;
      END
   END clk0
   PIN clk1
      DIRECTION INPUT ;
      PORT
         LAYER met4 ;
         RECT  1392.18 299.57 1392.56 299.95 ;
      END
   END clk1
   PIN dout1[0]
      DIRECTION OUTPUT ;
      PORT
         LAYER met4 ;
         RECT  312.285 299.57 312.665 299.95 ;
      END
   END dout1[0]
   PIN dout1[1]
      DIRECTION OUTPUT ;
      PORT
         LAYER met4 ;
         RECT  317.255 299.57 317.635 299.95 ;
      END
   END dout1[1]
   PIN dout1[2]
      DIRECTION OUTPUT ;
      PORT
         LAYER met4 ;
         RECT  318.525 299.57 318.905 299.95 ;
      END
   END dout1[2]
   PIN dout1[3]
      DIRECTION OUTPUT ;
      PORT
         LAYER met4 ;
         RECT  323.495 299.57 323.875 299.95 ;
      END
   END dout1[3]
   PIN dout1[4]
      DIRECTION OUTPUT ;
      PORT
         LAYER met4 ;
         RECT  324.765 299.57 325.145 299.95 ;
      END
   END dout1[4]
   PIN dout1[5]
      DIRECTION OUTPUT ;
      PORT
         LAYER met4 ;
         RECT  329.735 299.57 330.115 299.95 ;
      END
   END dout1[5]
   PIN dout1[6]
      DIRECTION OUTPUT ;
      PORT
         LAYER met4 ;
         RECT  331.005 299.57 331.385 299.95 ;
      END
   END dout1[6]
   PIN dout1[7]
      DIRECTION OUTPUT ;
      PORT
         LAYER met4 ;
         RECT  335.975 299.57 336.355 299.95 ;
      END
   END dout1[7]
   PIN dout1[8]
      DIRECTION OUTPUT ;
      PORT
         LAYER met4 ;
         RECT  337.245 299.57 337.625 299.95 ;
      END
   END dout1[8]
   PIN dout1[9]
      DIRECTION OUTPUT ;
      PORT
         LAYER met4 ;
         RECT  342.215 299.57 342.595 299.95 ;
      END
   END dout1[9]
   PIN dout1[10]
      DIRECTION OUTPUT ;
      PORT
         LAYER met4 ;
         RECT  343.485 299.57 343.865 299.95 ;
      END
   END dout1[10]
   PIN dout1[11]
      DIRECTION OUTPUT ;
      PORT
         LAYER met4 ;
         RECT  348.455 299.57 348.835 299.95 ;
      END
   END dout1[11]
   PIN dout1[12]
      DIRECTION OUTPUT ;
      PORT
         LAYER met4 ;
         RECT  349.725 299.57 350.105 299.95 ;
      END
   END dout1[12]
   PIN dout1[13]
      DIRECTION OUTPUT ;
      PORT
         LAYER met4 ;
         RECT  354.695 299.57 355.075 299.95 ;
      END
   END dout1[13]
   PIN dout1[14]
      DIRECTION OUTPUT ;
      PORT
         LAYER met4 ;
         RECT  355.965 299.57 356.345 299.95 ;
      END
   END dout1[14]
   PIN dout1[15]
      DIRECTION OUTPUT ;
      PORT
         LAYER met4 ;
         RECT  360.935 299.57 361.315 299.95 ;
      END
   END dout1[15]
   PIN dout1[16]
      DIRECTION OUTPUT ;
      PORT
         LAYER met4 ;
         RECT  362.205 299.57 362.585 299.95 ;
      END
   END dout1[16]
   PIN dout1[17]
      DIRECTION OUTPUT ;
      PORT
         LAYER met4 ;
         RECT  367.175 299.57 367.555 299.95 ;
      END
   END dout1[17]
   PIN dout1[18]
      DIRECTION OUTPUT ;
      PORT
         LAYER met4 ;
         RECT  368.445 299.57 368.825 299.95 ;
      END
   END dout1[18]
   PIN dout1[19]
      DIRECTION OUTPUT ;
      PORT
         LAYER met4 ;
         RECT  373.415 299.57 373.795 299.95 ;
      END
   END dout1[19]
   PIN dout1[20]
      DIRECTION OUTPUT ;
      PORT
         LAYER met4 ;
         RECT  374.685 299.57 375.065 299.95 ;
      END
   END dout1[20]
   PIN dout1[21]
      DIRECTION OUTPUT ;
      PORT
         LAYER met4 ;
         RECT  379.655 299.57 380.035 299.95 ;
      END
   END dout1[21]
   PIN dout1[22]
      DIRECTION OUTPUT ;
      PORT
         LAYER met4 ;
         RECT  380.925 299.57 381.305 299.95 ;
      END
   END dout1[22]
   PIN dout1[23]
      DIRECTION OUTPUT ;
      PORT
         LAYER met4 ;
         RECT  385.895 299.57 386.275 299.95 ;
      END
   END dout1[23]
   PIN dout1[24]
      DIRECTION OUTPUT ;
      PORT
         LAYER met4 ;
         RECT  387.165 299.57 387.545 299.95 ;
      END
   END dout1[24]
   PIN dout1[25]
      DIRECTION OUTPUT ;
      PORT
         LAYER met4 ;
         RECT  392.135 299.57 392.515 299.95 ;
      END
   END dout1[25]
   PIN dout1[26]
      DIRECTION OUTPUT ;
      PORT
         LAYER met4 ;
         RECT  393.405 299.57 393.785 299.95 ;
      END
   END dout1[26]
   PIN dout1[27]
      DIRECTION OUTPUT ;
      PORT
         LAYER met4 ;
         RECT  398.375 299.57 398.755 299.95 ;
      END
   END dout1[27]
   PIN dout1[28]
      DIRECTION OUTPUT ;
      PORT
         LAYER met4 ;
         RECT  399.645 299.57 400.025 299.95 ;
      END
   END dout1[28]
   PIN dout1[29]
      DIRECTION OUTPUT ;
      PORT
         LAYER met4 ;
         RECT  404.615 299.57 404.995 299.95 ;
      END
   END dout1[29]
   PIN dout1[30]
      DIRECTION OUTPUT ;
      PORT
         LAYER met4 ;
         RECT  405.885 299.57 406.265 299.95 ;
      END
   END dout1[30]
   PIN dout1[31]
      DIRECTION OUTPUT ;
      PORT
         LAYER met4 ;
         RECT  410.855 299.57 411.235 299.95 ;
      END
   END dout1[31]
   PIN dout1[32]
      DIRECTION OUTPUT ;
      PORT
         LAYER met4 ;
         RECT  412.125 299.57 412.505 299.95 ;
      END
   END dout1[32]
   PIN dout1[33]
      DIRECTION OUTPUT ;
      PORT
         LAYER met4 ;
         RECT  417.095 299.57 417.475 299.95 ;
      END
   END dout1[33]
   PIN dout1[34]
      DIRECTION OUTPUT ;
      PORT
         LAYER met4 ;
         RECT  418.365 299.57 418.745 299.95 ;
      END
   END dout1[34]
   PIN dout1[35]
      DIRECTION OUTPUT ;
      PORT
         LAYER met4 ;
         RECT  423.335 299.57 423.715 299.95 ;
      END
   END dout1[35]
   PIN dout1[36]
      DIRECTION OUTPUT ;
      PORT
         LAYER met4 ;
         RECT  424.605 299.57 424.985 299.95 ;
      END
   END dout1[36]
   PIN dout1[37]
      DIRECTION OUTPUT ;
      PORT
         LAYER met4 ;
         RECT  429.575 299.57 429.955 299.95 ;
      END
   END dout1[37]
   PIN dout1[38]
      DIRECTION OUTPUT ;
      PORT
         LAYER met4 ;
         RECT  430.845 299.57 431.225 299.95 ;
      END
   END dout1[38]
   PIN dout1[39]
      DIRECTION OUTPUT ;
      PORT
         LAYER met4 ;
         RECT  435.815 299.57 436.195 299.95 ;
      END
   END dout1[39]
   PIN dout1[40]
      DIRECTION OUTPUT ;
      PORT
         LAYER met4 ;
         RECT  437.085 299.57 437.465 299.95 ;
      END
   END dout1[40]
   PIN dout1[41]
      DIRECTION OUTPUT ;
      PORT
         LAYER met4 ;
         RECT  442.055 299.57 442.435 299.95 ;
      END
   END dout1[41]
   PIN dout1[42]
      DIRECTION OUTPUT ;
      PORT
         LAYER met4 ;
         RECT  443.325 299.57 443.705 299.95 ;
      END
   END dout1[42]
   PIN dout1[43]
      DIRECTION OUTPUT ;
      PORT
         LAYER met4 ;
         RECT  448.295 299.57 448.675 299.95 ;
      END
   END dout1[43]
   PIN dout1[44]
      DIRECTION OUTPUT ;
      PORT
         LAYER met4 ;
         RECT  449.565 299.57 449.945 299.95 ;
      END
   END dout1[44]
   PIN dout1[45]
      DIRECTION OUTPUT ;
      PORT
         LAYER met4 ;
         RECT  454.535 299.57 454.915 299.95 ;
      END
   END dout1[45]
   PIN dout1[46]
      DIRECTION OUTPUT ;
      PORT
         LAYER met4 ;
         RECT  455.805 299.57 456.185 299.95 ;
      END
   END dout1[46]
   PIN dout1[47]
      DIRECTION OUTPUT ;
      PORT
         LAYER met4 ;
         RECT  460.775 299.57 461.155 299.95 ;
      END
   END dout1[47]
   PIN dout1[48]
      DIRECTION OUTPUT ;
      PORT
         LAYER met4 ;
         RECT  462.045 299.57 462.425 299.95 ;
      END
   END dout1[48]
   PIN dout1[49]
      DIRECTION OUTPUT ;
      PORT
         LAYER met4 ;
         RECT  467.015 299.57 467.395 299.95 ;
      END
   END dout1[49]
   PIN dout1[50]
      DIRECTION OUTPUT ;
      PORT
         LAYER met4 ;
         RECT  468.285 299.57 468.665 299.95 ;
      END
   END dout1[50]
   PIN dout1[51]
      DIRECTION OUTPUT ;
      PORT
         LAYER met4 ;
         RECT  473.255 299.57 473.635 299.95 ;
      END
   END dout1[51]
   PIN dout1[52]
      DIRECTION OUTPUT ;
      PORT
         LAYER met4 ;
         RECT  474.525 299.57 474.905 299.95 ;
      END
   END dout1[52]
   PIN dout1[53]
      DIRECTION OUTPUT ;
      PORT
         LAYER met4 ;
         RECT  479.495 299.57 479.875 299.95 ;
      END
   END dout1[53]
   PIN dout1[54]
      DIRECTION OUTPUT ;
      PORT
         LAYER met4 ;
         RECT  480.765 299.57 481.145 299.95 ;
      END
   END dout1[54]
   PIN dout1[55]
      DIRECTION OUTPUT ;
      PORT
         LAYER met4 ;
         RECT  485.735 299.57 486.115 299.95 ;
      END
   END dout1[55]
   PIN dout1[56]
      DIRECTION OUTPUT ;
      PORT
         LAYER met4 ;
         RECT  487.005 299.57 487.385 299.95 ;
      END
   END dout1[56]
   PIN dout1[57]
      DIRECTION OUTPUT ;
      PORT
         LAYER met4 ;
         RECT  491.975 299.57 492.355 299.95 ;
      END
   END dout1[57]
   PIN dout1[58]
      DIRECTION OUTPUT ;
      PORT
         LAYER met4 ;
         RECT  493.245 299.57 493.625 299.95 ;
      END
   END dout1[58]
   PIN dout1[59]
      DIRECTION OUTPUT ;
      PORT
         LAYER met4 ;
         RECT  498.215 299.57 498.595 299.95 ;
      END
   END dout1[59]
   PIN dout1[60]
      DIRECTION OUTPUT ;
      PORT
         LAYER met4 ;
         RECT  499.485 299.57 499.865 299.95 ;
      END
   END dout1[60]
   PIN dout1[61]
      DIRECTION OUTPUT ;
      PORT
         LAYER met4 ;
         RECT  504.455 299.57 504.835 299.95 ;
      END
   END dout1[61]
   PIN dout1[62]
      DIRECTION OUTPUT ;
      PORT
         LAYER met4 ;
         RECT  505.725 299.57 506.105 299.95 ;
      END
   END dout1[62]
   PIN dout1[63]
      DIRECTION OUTPUT ;
      PORT
         LAYER met4 ;
         RECT  510.695 299.57 511.075 299.95 ;
      END
   END dout1[63]
   PIN dout1[64]
      DIRECTION OUTPUT ;
      PORT
         LAYER met4 ;
         RECT  511.965 299.57 512.345 299.95 ;
      END
   END dout1[64]
   PIN dout1[65]
      DIRECTION OUTPUT ;
      PORT
         LAYER met4 ;
         RECT  516.935 299.57 517.315 299.95 ;
      END
   END dout1[65]
   PIN dout1[66]
      DIRECTION OUTPUT ;
      PORT
         LAYER met4 ;
         RECT  518.205 299.57 518.585 299.95 ;
      END
   END dout1[66]
   PIN dout1[67]
      DIRECTION OUTPUT ;
      PORT
         LAYER met4 ;
         RECT  523.175 299.57 523.555 299.95 ;
      END
   END dout1[67]
   PIN dout1[68]
      DIRECTION OUTPUT ;
      PORT
         LAYER met4 ;
         RECT  524.445 299.57 524.825 299.95 ;
      END
   END dout1[68]
   PIN dout1[69]
      DIRECTION OUTPUT ;
      PORT
         LAYER met4 ;
         RECT  529.415 299.57 529.795 299.95 ;
      END
   END dout1[69]
   PIN dout1[70]
      DIRECTION OUTPUT ;
      PORT
         LAYER met4 ;
         RECT  530.685 299.57 531.065 299.95 ;
      END
   END dout1[70]
   PIN dout1[71]
      DIRECTION OUTPUT ;
      PORT
         LAYER met4 ;
         RECT  535.655 299.57 536.035 299.95 ;
      END
   END dout1[71]
   PIN dout1[72]
      DIRECTION OUTPUT ;
      PORT
         LAYER met4 ;
         RECT  536.925 299.57 537.305 299.95 ;
      END
   END dout1[72]
   PIN dout1[73]
      DIRECTION OUTPUT ;
      PORT
         LAYER met4 ;
         RECT  541.895 299.57 542.275 299.95 ;
      END
   END dout1[73]
   PIN dout1[74]
      DIRECTION OUTPUT ;
      PORT
         LAYER met4 ;
         RECT  543.165 299.57 543.545 299.95 ;
      END
   END dout1[74]
   PIN dout1[75]
      DIRECTION OUTPUT ;
      PORT
         LAYER met4 ;
         RECT  548.135 299.57 548.515 299.95 ;
      END
   END dout1[75]
   PIN dout1[76]
      DIRECTION OUTPUT ;
      PORT
         LAYER met4 ;
         RECT  549.405 299.57 549.785 299.95 ;
      END
   END dout1[76]
   PIN dout1[77]
      DIRECTION OUTPUT ;
      PORT
         LAYER met4 ;
         RECT  554.375 299.57 554.755 299.95 ;
      END
   END dout1[77]
   PIN dout1[78]
      DIRECTION OUTPUT ;
      PORT
         LAYER met4 ;
         RECT  555.645 299.57 556.025 299.95 ;
      END
   END dout1[78]
   PIN dout1[79]
      DIRECTION OUTPUT ;
      PORT
         LAYER met4 ;
         RECT  560.615 299.57 560.995 299.95 ;
      END
   END dout1[79]
   PIN dout1[80]
      DIRECTION OUTPUT ;
      PORT
         LAYER met4 ;
         RECT  561.885 299.57 562.265 299.95 ;
      END
   END dout1[80]
   PIN dout1[81]
      DIRECTION OUTPUT ;
      PORT
         LAYER met4 ;
         RECT  566.855 299.57 567.235 299.95 ;
      END
   END dout1[81]
   PIN dout1[82]
      DIRECTION OUTPUT ;
      PORT
         LAYER met4 ;
         RECT  568.125 299.57 568.505 299.95 ;
      END
   END dout1[82]
   PIN dout1[83]
      DIRECTION OUTPUT ;
      PORT
         LAYER met4 ;
         RECT  573.095 299.57 573.475 299.95 ;
      END
   END dout1[83]
   PIN dout1[84]
      DIRECTION OUTPUT ;
      PORT
         LAYER met4 ;
         RECT  574.365 299.57 574.745 299.95 ;
      END
   END dout1[84]
   PIN dout1[85]
      DIRECTION OUTPUT ;
      PORT
         LAYER met4 ;
         RECT  579.335 299.57 579.715 299.95 ;
      END
   END dout1[85]
   PIN dout1[86]
      DIRECTION OUTPUT ;
      PORT
         LAYER met4 ;
         RECT  580.605 299.57 580.985 299.95 ;
      END
   END dout1[86]
   PIN dout1[87]
      DIRECTION OUTPUT ;
      PORT
         LAYER met4 ;
         RECT  585.575 299.57 585.955 299.95 ;
      END
   END dout1[87]
   PIN dout1[88]
      DIRECTION OUTPUT ;
      PORT
         LAYER met4 ;
         RECT  586.845 299.57 587.225 299.95 ;
      END
   END dout1[88]
   PIN dout1[89]
      DIRECTION OUTPUT ;
      PORT
         LAYER met4 ;
         RECT  591.815 299.57 592.195 299.95 ;
      END
   END dout1[89]
   PIN dout1[90]
      DIRECTION OUTPUT ;
      PORT
         LAYER met4 ;
         RECT  593.085 299.57 593.465 299.95 ;
      END
   END dout1[90]
   PIN dout1[91]
      DIRECTION OUTPUT ;
      PORT
         LAYER met4 ;
         RECT  598.055 299.57 598.435 299.95 ;
      END
   END dout1[91]
   PIN dout1[92]
      DIRECTION OUTPUT ;
      PORT
         LAYER met4 ;
         RECT  599.325 299.57 599.705 299.95 ;
      END
   END dout1[92]
   PIN dout1[93]
      DIRECTION OUTPUT ;
      PORT
         LAYER met4 ;
         RECT  604.295 299.57 604.675 299.95 ;
      END
   END dout1[93]
   PIN dout1[94]
      DIRECTION OUTPUT ;
      PORT
         LAYER met4 ;
         RECT  605.565 299.57 605.945 299.95 ;
      END
   END dout1[94]
   PIN dout1[95]
      DIRECTION OUTPUT ;
      PORT
         LAYER met4 ;
         RECT  610.535 299.57 610.915 299.95 ;
      END
   END dout1[95]
   PIN dout1[96]
      DIRECTION OUTPUT ;
      PORT
         LAYER met4 ;
         RECT  611.805 299.57 612.185 299.95 ;
      END
   END dout1[96]
   PIN dout1[97]
      DIRECTION OUTPUT ;
      PORT
         LAYER met4 ;
         RECT  616.775 299.57 617.155 299.95 ;
      END
   END dout1[97]
   PIN dout1[98]
      DIRECTION OUTPUT ;
      PORT
         LAYER met4 ;
         RECT  618.045 299.57 618.425 299.95 ;
      END
   END dout1[98]
   PIN dout1[99]
      DIRECTION OUTPUT ;
      PORT
         LAYER met4 ;
         RECT  623.015 299.57 623.395 299.95 ;
      END
   END dout1[99]
   PIN dout1[100]
      DIRECTION OUTPUT ;
      PORT
         LAYER met4 ;
         RECT  624.285 299.57 624.665 299.95 ;
      END
   END dout1[100]
   PIN dout1[101]
      DIRECTION OUTPUT ;
      PORT
         LAYER met4 ;
         RECT  629.255 299.57 629.635 299.95 ;
      END
   END dout1[101]
   PIN dout1[102]
      DIRECTION OUTPUT ;
      PORT
         LAYER met4 ;
         RECT  630.525 299.57 630.905 299.95 ;
      END
   END dout1[102]
   PIN dout1[103]
      DIRECTION OUTPUT ;
      PORT
         LAYER met4 ;
         RECT  635.495 299.57 635.875 299.95 ;
      END
   END dout1[103]
   PIN dout1[104]
      DIRECTION OUTPUT ;
      PORT
         LAYER met4 ;
         RECT  636.765 299.57 637.145 299.95 ;
      END
   END dout1[104]
   PIN dout1[105]
      DIRECTION OUTPUT ;
      PORT
         LAYER met4 ;
         RECT  641.735 299.57 642.115 299.95 ;
      END
   END dout1[105]
   PIN dout1[106]
      DIRECTION OUTPUT ;
      PORT
         LAYER met4 ;
         RECT  643.005 299.57 643.385 299.95 ;
      END
   END dout1[106]
   PIN dout1[107]
      DIRECTION OUTPUT ;
      PORT
         LAYER met4 ;
         RECT  647.975 299.57 648.355 299.95 ;
      END
   END dout1[107]
   PIN dout1[108]
      DIRECTION OUTPUT ;
      PORT
         LAYER met4 ;
         RECT  649.245 299.57 649.625 299.95 ;
      END
   END dout1[108]
   PIN dout1[109]
      DIRECTION OUTPUT ;
      PORT
         LAYER met4 ;
         RECT  654.215 299.57 654.595 299.95 ;
      END
   END dout1[109]
   PIN dout1[110]
      DIRECTION OUTPUT ;
      PORT
         LAYER met4 ;
         RECT  655.485 299.57 655.865 299.95 ;
      END
   END dout1[110]
   PIN dout1[111]
      DIRECTION OUTPUT ;
      PORT
         LAYER met4 ;
         RECT  660.455 299.57 660.835 299.95 ;
      END
   END dout1[111]
   PIN dout1[112]
      DIRECTION OUTPUT ;
      PORT
         LAYER met4 ;
         RECT  661.725 299.57 662.105 299.95 ;
      END
   END dout1[112]
   PIN dout1[113]
      DIRECTION OUTPUT ;
      PORT
         LAYER met4 ;
         RECT  666.695 299.57 667.075 299.95 ;
      END
   END dout1[113]
   PIN dout1[114]
      DIRECTION OUTPUT ;
      PORT
         LAYER met4 ;
         RECT  667.965 299.57 668.345 299.95 ;
      END
   END dout1[114]
   PIN dout1[115]
      DIRECTION OUTPUT ;
      PORT
         LAYER met4 ;
         RECT  672.935 299.57 673.315 299.95 ;
      END
   END dout1[115]
   PIN dout1[116]
      DIRECTION OUTPUT ;
      PORT
         LAYER met4 ;
         RECT  674.205 299.57 674.585 299.95 ;
      END
   END dout1[116]
   PIN dout1[117]
      DIRECTION OUTPUT ;
      PORT
         LAYER met4 ;
         RECT  679.175 299.57 679.555 299.95 ;
      END
   END dout1[117]
   PIN dout1[118]
      DIRECTION OUTPUT ;
      PORT
         LAYER met4 ;
         RECT  680.445 299.57 680.825 299.95 ;
      END
   END dout1[118]
   PIN dout1[119]
      DIRECTION OUTPUT ;
      PORT
         LAYER met4 ;
         RECT  685.415 299.57 685.795 299.95 ;
      END
   END dout1[119]
   PIN dout1[120]
      DIRECTION OUTPUT ;
      PORT
         LAYER met4 ;
         RECT  686.685 299.57 687.065 299.95 ;
      END
   END dout1[120]
   PIN dout1[121]
      DIRECTION OUTPUT ;
      PORT
         LAYER met4 ;
         RECT  691.655 299.57 692.035 299.95 ;
      END
   END dout1[121]
   PIN dout1[122]
      DIRECTION OUTPUT ;
      PORT
         LAYER met4 ;
         RECT  692.925 299.57 693.305 299.95 ;
      END
   END dout1[122]
   PIN dout1[123]
      DIRECTION OUTPUT ;
      PORT
         LAYER met4 ;
         RECT  697.895 299.57 698.275 299.95 ;
      END
   END dout1[123]
   PIN dout1[124]
      DIRECTION OUTPUT ;
      PORT
         LAYER met4 ;
         RECT  699.165 299.57 699.545 299.95 ;
      END
   END dout1[124]
   PIN dout1[125]
      DIRECTION OUTPUT ;
      PORT
         LAYER met4 ;
         RECT  704.135 299.57 704.515 299.95 ;
      END
   END dout1[125]
   PIN dout1[126]
      DIRECTION OUTPUT ;
      PORT
         LAYER met4 ;
         RECT  705.405 299.57 705.785 299.95 ;
      END
   END dout1[126]
   PIN dout1[127]
      DIRECTION OUTPUT ;
      PORT
         LAYER met4 ;
         RECT  710.375 299.57 710.755 299.95 ;
      END
   END dout1[127]
   PIN dout1[128]
      DIRECTION OUTPUT ;
      PORT
         LAYER met4 ;
         RECT  711.645 299.57 712.025 299.95 ;
      END
   END dout1[128]
   PIN dout1[129]
      DIRECTION OUTPUT ;
      PORT
         LAYER met4 ;
         RECT  716.615 299.57 716.995 299.95 ;
      END
   END dout1[129]
   PIN dout1[130]
      DIRECTION OUTPUT ;
      PORT
         LAYER met4 ;
         RECT  717.885 299.57 718.265 299.95 ;
      END
   END dout1[130]
   PIN dout1[131]
      DIRECTION OUTPUT ;
      PORT
         LAYER met4 ;
         RECT  722.855 299.57 723.235 299.95 ;
      END
   END dout1[131]
   PIN dout1[132]
      DIRECTION OUTPUT ;
      PORT
         LAYER met4 ;
         RECT  724.125 299.57 724.505 299.95 ;
      END
   END dout1[132]
   PIN dout1[133]
      DIRECTION OUTPUT ;
      PORT
         LAYER met4 ;
         RECT  729.095 299.57 729.475 299.95 ;
      END
   END dout1[133]
   PIN dout1[134]
      DIRECTION OUTPUT ;
      PORT
         LAYER met4 ;
         RECT  730.365 299.57 730.745 299.95 ;
      END
   END dout1[134]
   PIN dout1[135]
      DIRECTION OUTPUT ;
      PORT
         LAYER met4 ;
         RECT  735.335 299.57 735.715 299.95 ;
      END
   END dout1[135]
   PIN dout1[136]
      DIRECTION OUTPUT ;
      PORT
         LAYER met4 ;
         RECT  736.605 299.57 736.985 299.95 ;
      END
   END dout1[136]
   PIN dout1[137]
      DIRECTION OUTPUT ;
      PORT
         LAYER met4 ;
         RECT  741.575 299.57 741.955 299.95 ;
      END
   END dout1[137]
   PIN dout1[138]
      DIRECTION OUTPUT ;
      PORT
         LAYER met4 ;
         RECT  742.845 299.57 743.225 299.95 ;
      END
   END dout1[138]
   PIN dout1[139]
      DIRECTION OUTPUT ;
      PORT
         LAYER met4 ;
         RECT  747.815 299.57 748.195 299.95 ;
      END
   END dout1[139]
   PIN dout1[140]
      DIRECTION OUTPUT ;
      PORT
         LAYER met4 ;
         RECT  749.085 299.57 749.465 299.95 ;
      END
   END dout1[140]
   PIN dout1[141]
      DIRECTION OUTPUT ;
      PORT
         LAYER met4 ;
         RECT  754.055 299.57 754.435 299.95 ;
      END
   END dout1[141]
   PIN dout1[142]
      DIRECTION OUTPUT ;
      PORT
         LAYER met4 ;
         RECT  755.325 299.57 755.705 299.95 ;
      END
   END dout1[142]
   PIN dout1[143]
      DIRECTION OUTPUT ;
      PORT
         LAYER met4 ;
         RECT  760.295 299.57 760.675 299.95 ;
      END
   END dout1[143]
   PIN dout1[144]
      DIRECTION OUTPUT ;
      PORT
         LAYER met4 ;
         RECT  761.565 299.57 761.945 299.95 ;
      END
   END dout1[144]
   PIN dout1[145]
      DIRECTION OUTPUT ;
      PORT
         LAYER met4 ;
         RECT  766.535 299.57 766.915 299.95 ;
      END
   END dout1[145]
   PIN dout1[146]
      DIRECTION OUTPUT ;
      PORT
         LAYER met4 ;
         RECT  767.805 299.57 768.185 299.95 ;
      END
   END dout1[146]
   PIN dout1[147]
      DIRECTION OUTPUT ;
      PORT
         LAYER met4 ;
         RECT  772.775 299.57 773.155 299.95 ;
      END
   END dout1[147]
   PIN dout1[148]
      DIRECTION OUTPUT ;
      PORT
         LAYER met4 ;
         RECT  774.045 299.57 774.425 299.95 ;
      END
   END dout1[148]
   PIN dout1[149]
      DIRECTION OUTPUT ;
      PORT
         LAYER met4 ;
         RECT  779.015 299.57 779.395 299.95 ;
      END
   END dout1[149]
   PIN dout1[150]
      DIRECTION OUTPUT ;
      PORT
         LAYER met4 ;
         RECT  780.285 299.57 780.665 299.95 ;
      END
   END dout1[150]
   PIN dout1[151]
      DIRECTION OUTPUT ;
      PORT
         LAYER met4 ;
         RECT  785.255 299.57 785.635 299.95 ;
      END
   END dout1[151]
   PIN dout1[152]
      DIRECTION OUTPUT ;
      PORT
         LAYER met4 ;
         RECT  786.525 299.57 786.905 299.95 ;
      END
   END dout1[152]
   PIN dout1[153]
      DIRECTION OUTPUT ;
      PORT
         LAYER met4 ;
         RECT  791.495 299.57 791.875 299.95 ;
      END
   END dout1[153]
   PIN dout1[154]
      DIRECTION OUTPUT ;
      PORT
         LAYER met4 ;
         RECT  792.765 299.57 793.145 299.95 ;
      END
   END dout1[154]
   PIN dout1[155]
      DIRECTION OUTPUT ;
      PORT
         LAYER met4 ;
         RECT  797.735 299.57 798.115 299.95 ;
      END
   END dout1[155]
   PIN dout1[156]
      DIRECTION OUTPUT ;
      PORT
         LAYER met4 ;
         RECT  799.005 299.57 799.385 299.95 ;
      END
   END dout1[156]
   PIN dout1[157]
      DIRECTION OUTPUT ;
      PORT
         LAYER met4 ;
         RECT  803.975 299.57 804.355 299.95 ;
      END
   END dout1[157]
   PIN dout1[158]
      DIRECTION OUTPUT ;
      PORT
         LAYER met4 ;
         RECT  805.245 299.57 805.625 299.95 ;
      END
   END dout1[158]
   PIN dout1[159]
      DIRECTION OUTPUT ;
      PORT
         LAYER met4 ;
         RECT  810.215 299.57 810.595 299.95 ;
      END
   END dout1[159]
   PIN dout1[160]
      DIRECTION OUTPUT ;
      PORT
         LAYER met4 ;
         RECT  811.485 299.57 811.865 299.95 ;
      END
   END dout1[160]
   PIN dout1[161]
      DIRECTION OUTPUT ;
      PORT
         LAYER met4 ;
         RECT  816.455 299.57 816.835 299.95 ;
      END
   END dout1[161]
   PIN dout1[162]
      DIRECTION OUTPUT ;
      PORT
         LAYER met4 ;
         RECT  817.725 299.57 818.105 299.95 ;
      END
   END dout1[162]
   PIN dout1[163]
      DIRECTION OUTPUT ;
      PORT
         LAYER met4 ;
         RECT  822.695 299.57 823.075 299.95 ;
      END
   END dout1[163]
   PIN dout1[164]
      DIRECTION OUTPUT ;
      PORT
         LAYER met4 ;
         RECT  823.965 299.57 824.345 299.95 ;
      END
   END dout1[164]
   PIN dout1[165]
      DIRECTION OUTPUT ;
      PORT
         LAYER met4 ;
         RECT  828.935 299.57 829.315 299.95 ;
      END
   END dout1[165]
   PIN dout1[166]
      DIRECTION OUTPUT ;
      PORT
         LAYER met4 ;
         RECT  830.205 299.57 830.585 299.95 ;
      END
   END dout1[166]
   PIN dout1[167]
      DIRECTION OUTPUT ;
      PORT
         LAYER met4 ;
         RECT  835.175 299.57 835.555 299.95 ;
      END
   END dout1[167]
   PIN dout1[168]
      DIRECTION OUTPUT ;
      PORT
         LAYER met4 ;
         RECT  836.445 299.57 836.825 299.95 ;
      END
   END dout1[168]
   PIN dout1[169]
      DIRECTION OUTPUT ;
      PORT
         LAYER met4 ;
         RECT  841.415 299.57 841.795 299.95 ;
      END
   END dout1[169]
   PIN dout1[170]
      DIRECTION OUTPUT ;
      PORT
         LAYER met4 ;
         RECT  842.685 299.57 843.065 299.95 ;
      END
   END dout1[170]
   PIN dout1[171]
      DIRECTION OUTPUT ;
      PORT
         LAYER met4 ;
         RECT  847.655 299.57 848.035 299.95 ;
      END
   END dout1[171]
   PIN dout1[172]
      DIRECTION OUTPUT ;
      PORT
         LAYER met4 ;
         RECT  848.925 299.57 849.305 299.95 ;
      END
   END dout1[172]
   PIN dout1[173]
      DIRECTION OUTPUT ;
      PORT
         LAYER met4 ;
         RECT  853.895 299.57 854.275 299.95 ;
      END
   END dout1[173]
   PIN dout1[174]
      DIRECTION OUTPUT ;
      PORT
         LAYER met4 ;
         RECT  855.165 299.57 855.545 299.95 ;
      END
   END dout1[174]
   PIN dout1[175]
      DIRECTION OUTPUT ;
      PORT
         LAYER met4 ;
         RECT  860.135 299.57 860.515 299.95 ;
      END
   END dout1[175]
   PIN dout1[176]
      DIRECTION OUTPUT ;
      PORT
         LAYER met4 ;
         RECT  861.405 299.57 861.785 299.95 ;
      END
   END dout1[176]
   PIN dout1[177]
      DIRECTION OUTPUT ;
      PORT
         LAYER met4 ;
         RECT  866.375 299.57 866.755 299.95 ;
      END
   END dout1[177]
   PIN dout1[178]
      DIRECTION OUTPUT ;
      PORT
         LAYER met4 ;
         RECT  867.645 299.57 868.025 299.95 ;
      END
   END dout1[178]
   PIN dout1[179]
      DIRECTION OUTPUT ;
      PORT
         LAYER met4 ;
         RECT  872.615 299.57 872.995 299.95 ;
      END
   END dout1[179]
   PIN dout1[180]
      DIRECTION OUTPUT ;
      PORT
         LAYER met4 ;
         RECT  873.885 299.57 874.265 299.95 ;
      END
   END dout1[180]
   PIN dout1[181]
      DIRECTION OUTPUT ;
      PORT
         LAYER met4 ;
         RECT  878.855 299.57 879.235 299.95 ;
      END
   END dout1[181]
   PIN dout1[182]
      DIRECTION OUTPUT ;
      PORT
         LAYER met4 ;
         RECT  880.125 299.57 880.505 299.95 ;
      END
   END dout1[182]
   PIN dout1[183]
      DIRECTION OUTPUT ;
      PORT
         LAYER met4 ;
         RECT  885.095 299.57 885.475 299.95 ;
      END
   END dout1[183]
   PIN dout1[184]
      DIRECTION OUTPUT ;
      PORT
         LAYER met4 ;
         RECT  886.365 299.57 886.745 299.95 ;
      END
   END dout1[184]
   PIN dout1[185]
      DIRECTION OUTPUT ;
      PORT
         LAYER met4 ;
         RECT  891.335 299.57 891.715 299.95 ;
      END
   END dout1[185]
   PIN dout1[186]
      DIRECTION OUTPUT ;
      PORT
         LAYER met4 ;
         RECT  892.605 299.57 892.985 299.95 ;
      END
   END dout1[186]
   PIN dout1[187]
      DIRECTION OUTPUT ;
      PORT
         LAYER met4 ;
         RECT  897.575 299.57 897.955 299.95 ;
      END
   END dout1[187]
   PIN dout1[188]
      DIRECTION OUTPUT ;
      PORT
         LAYER met4 ;
         RECT  898.845 299.57 899.225 299.95 ;
      END
   END dout1[188]
   PIN dout1[189]
      DIRECTION OUTPUT ;
      PORT
         LAYER met4 ;
         RECT  903.815 299.57 904.195 299.95 ;
      END
   END dout1[189]
   PIN dout1[190]
      DIRECTION OUTPUT ;
      PORT
         LAYER met4 ;
         RECT  905.085 299.57 905.465 299.95 ;
      END
   END dout1[190]
   PIN dout1[191]
      DIRECTION OUTPUT ;
      PORT
         LAYER met4 ;
         RECT  910.055 299.57 910.435 299.95 ;
      END
   END dout1[191]
   PIN dout1[192]
      DIRECTION OUTPUT ;
      PORT
         LAYER met4 ;
         RECT  911.325 299.57 911.705 299.95 ;
      END
   END dout1[192]
   PIN dout1[193]
      DIRECTION OUTPUT ;
      PORT
         LAYER met4 ;
         RECT  916.295 299.57 916.675 299.95 ;
      END
   END dout1[193]
   PIN dout1[194]
      DIRECTION OUTPUT ;
      PORT
         LAYER met4 ;
         RECT  917.565 299.57 917.945 299.95 ;
      END
   END dout1[194]
   PIN dout1[195]
      DIRECTION OUTPUT ;
      PORT
         LAYER met4 ;
         RECT  922.535 299.57 922.915 299.95 ;
      END
   END dout1[195]
   PIN dout1[196]
      DIRECTION OUTPUT ;
      PORT
         LAYER met4 ;
         RECT  923.805 299.57 924.185 299.95 ;
      END
   END dout1[196]
   PIN dout1[197]
      DIRECTION OUTPUT ;
      PORT
         LAYER met4 ;
         RECT  928.775 299.57 929.155 299.95 ;
      END
   END dout1[197]
   PIN dout1[198]
      DIRECTION OUTPUT ;
      PORT
         LAYER met4 ;
         RECT  930.045 299.57 930.425 299.95 ;
      END
   END dout1[198]
   PIN dout1[199]
      DIRECTION OUTPUT ;
      PORT
         LAYER met4 ;
         RECT  935.015 299.57 935.395 299.95 ;
      END
   END dout1[199]
   PIN dout1[200]
      DIRECTION OUTPUT ;
      PORT
         LAYER met4 ;
         RECT  936.285 299.57 936.665 299.95 ;
      END
   END dout1[200]
   PIN dout1[201]
      DIRECTION OUTPUT ;
      PORT
         LAYER met4 ;
         RECT  941.255 299.57 941.635 299.95 ;
      END
   END dout1[201]
   PIN dout1[202]
      DIRECTION OUTPUT ;
      PORT
         LAYER met4 ;
         RECT  942.525 299.57 942.905 299.95 ;
      END
   END dout1[202]
   PIN dout1[203]
      DIRECTION OUTPUT ;
      PORT
         LAYER met4 ;
         RECT  947.495 299.57 947.875 299.95 ;
      END
   END dout1[203]
   PIN dout1[204]
      DIRECTION OUTPUT ;
      PORT
         LAYER met4 ;
         RECT  948.765 299.57 949.145 299.95 ;
      END
   END dout1[204]
   PIN dout1[205]
      DIRECTION OUTPUT ;
      PORT
         LAYER met4 ;
         RECT  953.735 299.57 954.115 299.95 ;
      END
   END dout1[205]
   PIN dout1[206]
      DIRECTION OUTPUT ;
      PORT
         LAYER met4 ;
         RECT  955.005 299.57 955.385 299.95 ;
      END
   END dout1[206]
   PIN dout1[207]
      DIRECTION OUTPUT ;
      PORT
         LAYER met4 ;
         RECT  959.975 299.57 960.355 299.95 ;
      END
   END dout1[207]
   PIN dout1[208]
      DIRECTION OUTPUT ;
      PORT
         LAYER met4 ;
         RECT  961.245 299.57 961.625 299.95 ;
      END
   END dout1[208]
   PIN dout1[209]
      DIRECTION OUTPUT ;
      PORT
         LAYER met4 ;
         RECT  966.215 299.57 966.595 299.95 ;
      END
   END dout1[209]
   PIN dout1[210]
      DIRECTION OUTPUT ;
      PORT
         LAYER met4 ;
         RECT  967.485 299.57 967.865 299.95 ;
      END
   END dout1[210]
   PIN dout1[211]
      DIRECTION OUTPUT ;
      PORT
         LAYER met4 ;
         RECT  972.455 299.57 972.835 299.95 ;
      END
   END dout1[211]
   PIN dout1[212]
      DIRECTION OUTPUT ;
      PORT
         LAYER met4 ;
         RECT  973.725 299.57 974.105 299.95 ;
      END
   END dout1[212]
   PIN dout1[213]
      DIRECTION OUTPUT ;
      PORT
         LAYER met4 ;
         RECT  978.695 299.57 979.075 299.95 ;
      END
   END dout1[213]
   PIN dout1[214]
      DIRECTION OUTPUT ;
      PORT
         LAYER met4 ;
         RECT  979.965 299.57 980.345 299.95 ;
      END
   END dout1[214]
   PIN dout1[215]
      DIRECTION OUTPUT ;
      PORT
         LAYER met4 ;
         RECT  984.935 299.57 985.315 299.95 ;
      END
   END dout1[215]
   PIN dout1[216]
      DIRECTION OUTPUT ;
      PORT
         LAYER met4 ;
         RECT  986.205 299.57 986.585 299.95 ;
      END
   END dout1[216]
   PIN dout1[217]
      DIRECTION OUTPUT ;
      PORT
         LAYER met4 ;
         RECT  991.175 299.57 991.555 299.95 ;
      END
   END dout1[217]
   PIN dout1[218]
      DIRECTION OUTPUT ;
      PORT
         LAYER met4 ;
         RECT  992.445 299.57 992.825 299.95 ;
      END
   END dout1[218]
   PIN dout1[219]
      DIRECTION OUTPUT ;
      PORT
         LAYER met4 ;
         RECT  997.415 299.57 997.795 299.95 ;
      END
   END dout1[219]
   PIN dout1[220]
      DIRECTION OUTPUT ;
      PORT
         LAYER met4 ;
         RECT  998.685 299.57 999.065 299.95 ;
      END
   END dout1[220]
   PIN dout1[221]
      DIRECTION OUTPUT ;
      PORT
         LAYER met4 ;
         RECT  1003.655 299.57 1004.035 299.95 ;
      END
   END dout1[221]
   PIN dout1[222]
      DIRECTION OUTPUT ;
      PORT
         LAYER met4 ;
         RECT  1004.925 299.57 1005.305 299.95 ;
      END
   END dout1[222]
   PIN dout1[223]
      DIRECTION OUTPUT ;
      PORT
         LAYER met4 ;
         RECT  1009.895 299.57 1010.275 299.95 ;
      END
   END dout1[223]
   PIN dout1[224]
      DIRECTION OUTPUT ;
      PORT
         LAYER met4 ;
         RECT  1011.165 299.57 1011.545 299.95 ;
      END
   END dout1[224]
   PIN dout1[225]
      DIRECTION OUTPUT ;
      PORT
         LAYER met4 ;
         RECT  1016.135 299.57 1016.515 299.95 ;
      END
   END dout1[225]
   PIN dout1[226]
      DIRECTION OUTPUT ;
      PORT
         LAYER met4 ;
         RECT  1017.405 299.57 1017.785 299.95 ;
      END
   END dout1[226]
   PIN dout1[227]
      DIRECTION OUTPUT ;
      PORT
         LAYER met4 ;
         RECT  1022.375 299.57 1022.755 299.95 ;
      END
   END dout1[227]
   PIN dout1[228]
      DIRECTION OUTPUT ;
      PORT
         LAYER met4 ;
         RECT  1023.645 299.57 1024.025 299.95 ;
      END
   END dout1[228]
   PIN dout1[229]
      DIRECTION OUTPUT ;
      PORT
         LAYER met4 ;
         RECT  1028.615 299.57 1028.995 299.95 ;
      END
   END dout1[229]
   PIN dout1[230]
      DIRECTION OUTPUT ;
      PORT
         LAYER met4 ;
         RECT  1029.885 299.57 1030.265 299.95 ;
      END
   END dout1[230]
   PIN dout1[231]
      DIRECTION OUTPUT ;
      PORT
         LAYER met4 ;
         RECT  1034.855 299.57 1035.235 299.95 ;
      END
   END dout1[231]
   PIN dout1[232]
      DIRECTION OUTPUT ;
      PORT
         LAYER met4 ;
         RECT  1036.125 299.57 1036.505 299.95 ;
      END
   END dout1[232]
   PIN dout1[233]
      DIRECTION OUTPUT ;
      PORT
         LAYER met4 ;
         RECT  1041.095 299.57 1041.475 299.95 ;
      END
   END dout1[233]
   PIN dout1[234]
      DIRECTION OUTPUT ;
      PORT
         LAYER met4 ;
         RECT  1042.365 299.57 1042.745 299.95 ;
      END
   END dout1[234]
   PIN dout1[235]
      DIRECTION OUTPUT ;
      PORT
         LAYER met4 ;
         RECT  1047.335 299.57 1047.715 299.95 ;
      END
   END dout1[235]
   PIN dout1[236]
      DIRECTION OUTPUT ;
      PORT
         LAYER met4 ;
         RECT  1048.605 299.57 1048.985 299.95 ;
      END
   END dout1[236]
   PIN dout1[237]
      DIRECTION OUTPUT ;
      PORT
         LAYER met4 ;
         RECT  1053.575 299.57 1053.955 299.95 ;
      END
   END dout1[237]
   PIN dout1[238]
      DIRECTION OUTPUT ;
      PORT
         LAYER met4 ;
         RECT  1054.845 299.57 1055.225 299.95 ;
      END
   END dout1[238]
   PIN dout1[239]
      DIRECTION OUTPUT ;
      PORT
         LAYER met4 ;
         RECT  1059.815 299.57 1060.195 299.95 ;
      END
   END dout1[239]
   PIN dout1[240]
      DIRECTION OUTPUT ;
      PORT
         LAYER met4 ;
         RECT  1061.085 299.57 1061.465 299.95 ;
      END
   END dout1[240]
   PIN dout1[241]
      DIRECTION OUTPUT ;
      PORT
         LAYER met4 ;
         RECT  1066.055 299.57 1066.435 299.95 ;
      END
   END dout1[241]
   PIN dout1[242]
      DIRECTION OUTPUT ;
      PORT
         LAYER met4 ;
         RECT  1067.325 299.57 1067.705 299.95 ;
      END
   END dout1[242]
   PIN dout1[243]
      DIRECTION OUTPUT ;
      PORT
         LAYER met4 ;
         RECT  1072.295 299.57 1072.675 299.95 ;
      END
   END dout1[243]
   PIN dout1[244]
      DIRECTION OUTPUT ;
      PORT
         LAYER met4 ;
         RECT  1073.565 299.57 1073.945 299.95 ;
      END
   END dout1[244]
   PIN dout1[245]
      DIRECTION OUTPUT ;
      PORT
         LAYER met4 ;
         RECT  1078.535 299.57 1078.915 299.95 ;
      END
   END dout1[245]
   PIN dout1[246]
      DIRECTION OUTPUT ;
      PORT
         LAYER met4 ;
         RECT  1079.805 299.57 1080.185 299.95 ;
      END
   END dout1[246]
   PIN dout1[247]
      DIRECTION OUTPUT ;
      PORT
         LAYER met4 ;
         RECT  1084.775 299.57 1085.155 299.95 ;
      END
   END dout1[247]
   PIN dout1[248]
      DIRECTION OUTPUT ;
      PORT
         LAYER met4 ;
         RECT  1086.045 299.57 1086.425 299.95 ;
      END
   END dout1[248]
   PIN dout1[249]
      DIRECTION OUTPUT ;
      PORT
         LAYER met4 ;
         RECT  1091.015 299.57 1091.395 299.95 ;
      END
   END dout1[249]
   PIN dout1[250]
      DIRECTION OUTPUT ;
      PORT
         LAYER met4 ;
         RECT  1092.285 299.57 1092.665 299.95 ;
      END
   END dout1[250]
   PIN dout1[251]
      DIRECTION OUTPUT ;
      PORT
         LAYER met4 ;
         RECT  1097.255 299.57 1097.635 299.95 ;
      END
   END dout1[251]
   PIN dout1[252]
      DIRECTION OUTPUT ;
      PORT
         LAYER met4 ;
         RECT  1098.525 299.57 1098.905 299.95 ;
      END
   END dout1[252]
   PIN dout1[253]
      DIRECTION OUTPUT ;
      PORT
         LAYER met4 ;
         RECT  1103.495 299.57 1103.875 299.95 ;
      END
   END dout1[253]
   PIN dout1[254]
      DIRECTION OUTPUT ;
      PORT
         LAYER met4 ;
         RECT  1104.765 299.57 1105.145 299.95 ;
      END
   END dout1[254]
   PIN dout1[255]
      DIRECTION OUTPUT ;
      PORT
         LAYER met4 ;
         RECT  1109.735 299.57 1110.115 299.95 ;
      END
   END dout1[255]
   PIN vccd1
      DIRECTION INOUT ;
      USE POWER ; 
      SHAPE ABUTMENT ; 
      PORT
         LAYER met3 ;
         RECT  0.0 0.0 1754.92 1.74 ;
         LAYER met4 ;
         RECT  1753.18 0.0 1754.92 299.95 ;
         LAYER met4 ;
         RECT  0.0 0.0 1.74 299.95 ;
         LAYER met3 ;
         RECT  0.0 298.21 1754.92 299.95 ;
      END
   END vccd1
   PIN vssd1
      DIRECTION INOUT ;
      USE GROUND ; 
      SHAPE ABUTMENT ; 
      PORT
         LAYER met3 ;
         RECT  3.48 3.48 1751.44 5.22 ;
         LAYER met4 ;
         RECT  1749.7 3.48 1751.44 296.47 ;
         LAYER met4 ;
         RECT  3.48 3.48 5.22 296.47 ;
         LAYER met3 ;
         RECT  3.48 294.73 1751.44 296.47 ;
      END
   END vssd1
   OBS
   LAYER  met1 ;
      RECT  0.62 0.62 1754.3 299.33 ;
   LAYER  met2 ;
      RECT  0.62 0.62 1754.3 299.33 ;
   LAYER  met3 ;
      RECT  0.98 122.835 1754.3 124.415 ;
      RECT  0.62 2.34 0.98 122.835 ;
      RECT  0.62 125.16 0.98 297.61 ;
      RECT  0.98 2.34 2.88 2.88 ;
      RECT  0.98 2.88 2.88 5.82 ;
      RECT  0.98 5.82 2.88 122.835 ;
      RECT  2.88 2.34 1752.04 2.88 ;
      RECT  2.88 5.82 1752.04 122.835 ;
      RECT  1752.04 2.34 1754.3 2.88 ;
      RECT  1752.04 2.88 1754.3 5.82 ;
      RECT  1752.04 5.82 1754.3 122.835 ;
      RECT  0.98 124.415 2.88 294.13 ;
      RECT  0.98 294.13 2.88 297.07 ;
      RECT  0.98 297.07 2.88 297.61 ;
      RECT  2.88 124.415 1752.04 294.13 ;
      RECT  2.88 297.07 1752.04 297.61 ;
      RECT  1752.04 124.415 1754.3 294.13 ;
      RECT  1752.04 294.13 1754.3 297.07 ;
      RECT  1752.04 297.07 1754.3 297.61 ;
   LAYER  met4 ;
      RECT  247.7 0.98 249.28 299.33 ;
      RECT  249.28 0.62 253.54 0.98 ;
      RECT  255.12 0.62 259.38 0.98 ;
      RECT  260.96 0.62 265.22 0.98 ;
      RECT  266.8 0.62 271.06 0.98 ;
      RECT  272.64 0.62 276.9 0.98 ;
      RECT  278.48 0.62 282.74 0.98 ;
      RECT  284.32 0.62 288.58 0.98 ;
      RECT  290.16 0.62 294.42 0.98 ;
      RECT  296.0 0.62 300.26 0.98 ;
      RECT  301.84 0.62 306.1 0.98 ;
      RECT  307.68 0.62 311.94 0.98 ;
      RECT  313.52 0.62 317.78 0.98 ;
      RECT  319.36 0.62 323.62 0.98 ;
      RECT  325.2 0.62 329.46 0.98 ;
      RECT  331.04 0.62 335.3 0.98 ;
      RECT  336.88 0.62 341.14 0.98 ;
      RECT  342.72 0.62 346.98 0.98 ;
      RECT  348.56 0.62 352.82 0.98 ;
      RECT  354.4 0.62 358.66 0.98 ;
      RECT  360.24 0.62 364.5 0.98 ;
      RECT  366.08 0.62 370.34 0.98 ;
      RECT  371.92 0.62 376.18 0.98 ;
      RECT  377.76 0.62 382.02 0.98 ;
      RECT  383.6 0.62 387.86 0.98 ;
      RECT  389.44 0.62 393.7 0.98 ;
      RECT  395.28 0.62 399.54 0.98 ;
      RECT  401.12 0.62 405.38 0.98 ;
      RECT  406.96 0.62 411.22 0.98 ;
      RECT  412.8 0.62 417.06 0.98 ;
      RECT  418.64 0.62 422.9 0.98 ;
      RECT  424.48 0.62 428.74 0.98 ;
      RECT  430.32 0.62 434.58 0.98 ;
      RECT  436.16 0.62 440.42 0.98 ;
      RECT  442.0 0.62 446.26 0.98 ;
      RECT  447.84 0.62 452.1 0.98 ;
      RECT  453.68 0.62 457.94 0.98 ;
      RECT  459.52 0.62 463.78 0.98 ;
      RECT  465.36 0.62 469.62 0.98 ;
      RECT  471.2 0.62 475.46 0.98 ;
      RECT  477.04 0.62 481.3 0.98 ;
      RECT  482.88 0.62 487.14 0.98 ;
      RECT  488.72 0.62 492.98 0.98 ;
      RECT  494.56 0.62 498.82 0.98 ;
      RECT  500.4 0.62 504.66 0.98 ;
      RECT  506.24 0.62 510.5 0.98 ;
      RECT  512.08 0.62 516.34 0.98 ;
      RECT  517.92 0.62 522.18 0.98 ;
      RECT  523.76 0.62 528.02 0.98 ;
      RECT  529.6 0.62 533.86 0.98 ;
      RECT  535.44 0.62 539.7 0.98 ;
      RECT  541.28 0.62 545.54 0.98 ;
      RECT  547.12 0.62 551.38 0.98 ;
      RECT  552.96 0.62 557.22 0.98 ;
      RECT  558.8 0.62 563.06 0.98 ;
      RECT  564.64 0.62 568.9 0.98 ;
      RECT  570.48 0.62 574.74 0.98 ;
      RECT  576.32 0.62 580.58 0.98 ;
      RECT  582.16 0.62 586.42 0.98 ;
      RECT  588.0 0.62 592.26 0.98 ;
      RECT  593.84 0.62 598.1 0.98 ;
      RECT  599.68 0.62 603.94 0.98 ;
      RECT  605.52 0.62 609.78 0.98 ;
      RECT  611.36 0.62 615.62 0.98 ;
      RECT  617.2 0.62 621.46 0.98 ;
      RECT  623.04 0.62 627.3 0.98 ;
      RECT  628.88 0.62 633.14 0.98 ;
      RECT  634.72 0.62 638.98 0.98 ;
      RECT  640.56 0.62 644.82 0.98 ;
      RECT  646.4 0.62 650.66 0.98 ;
      RECT  652.24 0.62 656.5 0.98 ;
      RECT  658.08 0.62 662.34 0.98 ;
      RECT  663.92 0.62 668.18 0.98 ;
      RECT  669.76 0.62 674.02 0.98 ;
      RECT  675.6 0.62 679.86 0.98 ;
      RECT  681.44 0.62 685.7 0.98 ;
      RECT  687.28 0.62 691.54 0.98 ;
      RECT  693.12 0.62 697.38 0.98 ;
      RECT  698.96 0.62 703.22 0.98 ;
      RECT  704.8 0.62 709.06 0.98 ;
      RECT  710.64 0.62 714.9 0.98 ;
      RECT  716.48 0.62 720.74 0.98 ;
      RECT  722.32 0.62 726.58 0.98 ;
      RECT  728.16 0.62 732.42 0.98 ;
      RECT  734.0 0.62 738.26 0.98 ;
      RECT  739.84 0.62 744.1 0.98 ;
      RECT  745.68 0.62 749.94 0.98 ;
      RECT  751.52 0.62 755.78 0.98 ;
      RECT  757.36 0.62 761.62 0.98 ;
      RECT  763.2 0.62 767.46 0.98 ;
      RECT  769.04 0.62 773.3 0.98 ;
      RECT  774.88 0.62 779.14 0.98 ;
      RECT  780.72 0.62 784.98 0.98 ;
      RECT  786.56 0.62 790.82 0.98 ;
      RECT  792.4 0.62 796.66 0.98 ;
      RECT  798.24 0.62 802.5 0.98 ;
      RECT  804.08 0.62 808.34 0.98 ;
      RECT  809.92 0.62 814.18 0.98 ;
      RECT  815.76 0.62 820.02 0.98 ;
      RECT  821.6 0.62 825.86 0.98 ;
      RECT  827.44 0.62 831.7 0.98 ;
      RECT  833.28 0.62 837.54 0.98 ;
      RECT  839.12 0.62 843.38 0.98 ;
      RECT  844.96 0.62 849.22 0.98 ;
      RECT  850.8 0.62 855.06 0.98 ;
      RECT  856.64 0.62 860.9 0.98 ;
      RECT  862.48 0.62 866.74 0.98 ;
      RECT  868.32 0.62 872.58 0.98 ;
      RECT  874.16 0.62 878.42 0.98 ;
      RECT  880.0 0.62 884.26 0.98 ;
      RECT  885.84 0.62 890.1 0.98 ;
      RECT  891.68 0.62 895.94 0.98 ;
      RECT  897.52 0.62 901.78 0.98 ;
      RECT  903.36 0.62 907.62 0.98 ;
      RECT  909.2 0.62 913.46 0.98 ;
      RECT  915.04 0.62 919.3 0.98 ;
      RECT  920.88 0.62 925.14 0.98 ;
      RECT  926.72 0.62 930.98 0.98 ;
      RECT  932.56 0.62 936.82 0.98 ;
      RECT  938.4 0.62 942.66 0.98 ;
      RECT  944.24 0.62 948.5 0.98 ;
      RECT  950.08 0.62 954.34 0.98 ;
      RECT  955.92 0.62 960.18 0.98 ;
      RECT  961.76 0.62 966.02 0.98 ;
      RECT  967.6 0.62 971.86 0.98 ;
      RECT  973.44 0.62 977.7 0.98 ;
      RECT  979.28 0.62 983.54 0.98 ;
      RECT  985.12 0.62 989.38 0.98 ;
      RECT  990.96 0.62 995.22 0.98 ;
      RECT  996.8 0.62 1001.06 0.98 ;
      RECT  1002.64 0.62 1006.9 0.98 ;
      RECT  1008.48 0.62 1012.74 0.98 ;
      RECT  1014.32 0.62 1018.58 0.98 ;
      RECT  1020.16 0.62 1024.42 0.98 ;
      RECT  1026.0 0.62 1030.26 0.98 ;
      RECT  1031.84 0.62 1036.1 0.98 ;
      RECT  1037.68 0.62 1041.94 0.98 ;
      RECT  1043.52 0.62 1047.78 0.98 ;
      RECT  1049.36 0.62 1053.62 0.98 ;
      RECT  1055.2 0.62 1059.46 0.98 ;
      RECT  1061.04 0.62 1065.3 0.98 ;
      RECT  1066.88 0.62 1071.14 0.98 ;
      RECT  1072.72 0.62 1076.98 0.98 ;
      RECT  1078.56 0.62 1082.82 0.98 ;
      RECT  1084.4 0.62 1088.66 0.98 ;
      RECT  1090.24 0.62 1094.5 0.98 ;
      RECT  1096.08 0.62 1100.34 0.98 ;
      RECT  1101.92 0.62 1106.18 0.98 ;
      RECT  1107.76 0.62 1112.02 0.98 ;
      RECT  1113.6 0.62 1117.86 0.98 ;
      RECT  1119.44 0.62 1123.7 0.98 ;
      RECT  1125.28 0.62 1129.54 0.98 ;
      RECT  1131.12 0.62 1135.38 0.98 ;
      RECT  1136.96 0.62 1141.22 0.98 ;
      RECT  1142.8 0.62 1147.06 0.98 ;
      RECT  1148.64 0.62 1152.9 0.98 ;
      RECT  1154.48 0.62 1158.74 0.98 ;
      RECT  1160.32 0.62 1164.58 0.98 ;
      RECT  1166.16 0.62 1170.42 0.98 ;
      RECT  1172.0 0.62 1176.26 0.98 ;
      RECT  1177.84 0.62 1182.1 0.98 ;
      RECT  1189.52 0.62 1193.78 0.98 ;
      RECT  1195.36 0.62 1199.62 0.98 ;
      RECT  1201.2 0.62 1205.46 0.98 ;
      RECT  1207.04 0.62 1211.3 0.98 ;
      RECT  1212.88 0.62 1217.14 0.98 ;
      RECT  1218.72 0.62 1222.98 0.98 ;
      RECT  1224.56 0.62 1228.82 0.98 ;
      RECT  1230.4 0.62 1234.66 0.98 ;
      RECT  1236.24 0.62 1240.5 0.98 ;
      RECT  1242.08 0.62 1246.34 0.98 ;
      RECT  1247.92 0.62 1252.18 0.98 ;
      RECT  1253.76 0.62 1258.02 0.98 ;
      RECT  1259.6 0.62 1263.86 0.98 ;
      RECT  1265.44 0.62 1269.7 0.98 ;
      RECT  1271.28 0.62 1275.54 0.98 ;
      RECT  1277.12 0.62 1281.38 0.98 ;
      RECT  1282.96 0.62 1287.22 0.98 ;
      RECT  1288.8 0.62 1293.06 0.98 ;
      RECT  1294.64 0.62 1298.9 0.98 ;
      RECT  1300.48 0.62 1304.74 0.98 ;
      RECT  1306.32 0.62 1310.58 0.98 ;
      RECT  1312.16 0.62 1316.42 0.98 ;
      RECT  1318.0 0.62 1322.26 0.98 ;
      RECT  1323.84 0.62 1328.1 0.98 ;
      RECT  1329.68 0.62 1333.94 0.98 ;
      RECT  1335.52 0.62 1339.78 0.98 ;
      RECT  1341.36 0.62 1345.62 0.98 ;
      RECT  1347.2 0.62 1351.46 0.98 ;
      RECT  1353.04 0.62 1357.3 0.98 ;
      RECT  1358.88 0.62 1363.14 0.98 ;
      RECT  1364.72 0.62 1368.98 0.98 ;
      RECT  1370.56 0.62 1374.82 0.98 ;
      RECT  1376.4 0.62 1380.66 0.98 ;
      RECT  1382.24 0.62 1386.5 0.98 ;
      RECT  1388.08 0.62 1392.34 0.98 ;
      RECT  1393.92 0.62 1398.18 0.98 ;
      RECT  1399.76 0.62 1404.02 0.98 ;
      RECT  1405.6 0.62 1409.86 0.98 ;
      RECT  1411.44 0.62 1415.7 0.98 ;
      RECT  1417.28 0.62 1421.54 0.98 ;
      RECT  1423.12 0.62 1427.38 0.98 ;
      RECT  1428.96 0.62 1433.22 0.98 ;
      RECT  1434.8 0.62 1439.06 0.98 ;
      RECT  1440.64 0.62 1444.9 0.98 ;
      RECT  1446.48 0.62 1450.74 0.98 ;
      RECT  1452.32 0.62 1456.58 0.98 ;
      RECT  1458.16 0.62 1462.42 0.98 ;
      RECT  1464.0 0.62 1468.26 0.98 ;
      RECT  1469.84 0.62 1474.1 0.98 ;
      RECT  1475.68 0.62 1479.94 0.98 ;
      RECT  1481.52 0.62 1485.78 0.98 ;
      RECT  1487.36 0.62 1491.62 0.98 ;
      RECT  1493.2 0.62 1497.46 0.98 ;
      RECT  1499.04 0.62 1503.3 0.98 ;
      RECT  1504.88 0.62 1509.14 0.98 ;
      RECT  1510.72 0.62 1514.98 0.98 ;
      RECT  1516.56 0.62 1520.82 0.98 ;
      RECT  1522.4 0.62 1526.66 0.98 ;
      RECT  1528.24 0.62 1532.5 0.98 ;
      RECT  1534.08 0.62 1538.34 0.98 ;
      RECT  1539.92 0.62 1544.18 0.98 ;
      RECT  1545.76 0.62 1550.02 0.98 ;
      RECT  1551.6 0.62 1555.86 0.98 ;
      RECT  1557.44 0.62 1561.7 0.98 ;
      RECT  1563.28 0.62 1567.54 0.98 ;
      RECT  1569.12 0.62 1573.38 0.98 ;
      RECT  1574.96 0.62 1579.22 0.98 ;
      RECT  1580.8 0.62 1585.06 0.98 ;
      RECT  1586.64 0.62 1590.9 0.98 ;
      RECT  1592.48 0.62 1596.74 0.98 ;
      RECT  1598.32 0.62 1602.58 0.98 ;
      RECT  1604.16 0.62 1608.42 0.98 ;
      RECT  1610.0 0.62 1614.26 0.98 ;
      RECT  1615.84 0.62 1620.1 0.98 ;
      RECT  1621.68 0.62 1625.94 0.98 ;
      RECT  1627.52 0.62 1631.78 0.98 ;
      RECT  1633.36 0.62 1637.62 0.98 ;
      RECT  1639.2 0.62 1643.46 0.98 ;
      RECT  1645.04 0.62 1649.3 0.98 ;
      RECT  1650.88 0.62 1655.14 0.98 ;
      RECT  1656.72 0.62 1660.98 0.98 ;
      RECT  1662.56 0.62 1666.82 0.98 ;
      RECT  1668.4 0.62 1672.66 0.98 ;
      RECT  1674.24 0.62 1678.5 0.98 ;
      RECT  1680.08 0.62 1684.34 0.98 ;
      RECT  1685.92 0.62 1690.18 0.98 ;
      RECT  1691.76 0.62 1696.02 0.98 ;
      RECT  1697.6 0.62 1701.86 0.98 ;
      RECT  1703.44 0.62 1707.7 0.98 ;
      RECT  1709.28 0.62 1713.54 0.98 ;
      RECT  1715.12 0.62 1719.38 0.98 ;
      RECT  1720.96 0.62 1725.22 0.98 ;
      RECT  1726.8 0.62 1731.06 0.98 ;
      RECT  1732.64 0.62 1736.9 0.98 ;
      RECT  238.145 0.98 239.725 298.97 ;
      RECT  239.725 0.98 247.7 298.97 ;
      RECT  239.725 298.97 247.7 299.33 ;
      RECT  249.28 0.98 1185.22 298.97 ;
      RECT  1185.22 0.98 1186.8 298.97 ;
      RECT  1183.68 0.62 1184.53 0.98 ;
      RECT  1186.8 0.62 1187.94 0.98 ;
      RECT  1186.8 298.97 1391.58 299.33 ;
      RECT  1393.16 298.97 1408.35 299.33 ;
      RECT  249.28 298.97 311.685 299.33 ;
      RECT  313.265 298.97 316.655 299.33 ;
      RECT  319.505 298.97 322.895 299.33 ;
      RECT  325.745 298.97 329.135 299.33 ;
      RECT  331.985 298.97 335.375 299.33 ;
      RECT  338.225 298.97 341.615 299.33 ;
      RECT  344.465 298.97 347.855 299.33 ;
      RECT  350.705 298.97 354.095 299.33 ;
      RECT  356.945 298.97 360.335 299.33 ;
      RECT  363.185 298.97 366.575 299.33 ;
      RECT  369.425 298.97 372.815 299.33 ;
      RECT  375.665 298.97 379.055 299.33 ;
      RECT  381.905 298.97 385.295 299.33 ;
      RECT  388.145 298.97 391.535 299.33 ;
      RECT  394.385 298.97 397.775 299.33 ;
      RECT  400.625 298.97 404.015 299.33 ;
      RECT  406.865 298.97 410.255 299.33 ;
      RECT  413.105 298.97 416.495 299.33 ;
      RECT  419.345 298.97 422.735 299.33 ;
      RECT  425.585 298.97 428.975 299.33 ;
      RECT  431.825 298.97 435.215 299.33 ;
      RECT  438.065 298.97 441.455 299.33 ;
      RECT  444.305 298.97 447.695 299.33 ;
      RECT  450.545 298.97 453.935 299.33 ;
      RECT  456.785 298.97 460.175 299.33 ;
      RECT  463.025 298.97 466.415 299.33 ;
      RECT  469.265 298.97 472.655 299.33 ;
      RECT  475.505 298.97 478.895 299.33 ;
      RECT  481.745 298.97 485.135 299.33 ;
      RECT  487.985 298.97 491.375 299.33 ;
      RECT  494.225 298.97 497.615 299.33 ;
      RECT  500.465 298.97 503.855 299.33 ;
      RECT  506.705 298.97 510.095 299.33 ;
      RECT  512.945 298.97 516.335 299.33 ;
      RECT  519.185 298.97 522.575 299.33 ;
      RECT  525.425 298.97 528.815 299.33 ;
      RECT  531.665 298.97 535.055 299.33 ;
      RECT  537.905 298.97 541.295 299.33 ;
      RECT  544.145 298.97 547.535 299.33 ;
      RECT  550.385 298.97 553.775 299.33 ;
      RECT  556.625 298.97 560.015 299.33 ;
      RECT  562.865 298.97 566.255 299.33 ;
      RECT  569.105 298.97 572.495 299.33 ;
      RECT  575.345 298.97 578.735 299.33 ;
      RECT  581.585 298.97 584.975 299.33 ;
      RECT  587.825 298.97 591.215 299.33 ;
      RECT  594.065 298.97 597.455 299.33 ;
      RECT  600.305 298.97 603.695 299.33 ;
      RECT  606.545 298.97 609.935 299.33 ;
      RECT  612.785 298.97 616.175 299.33 ;
      RECT  619.025 298.97 622.415 299.33 ;
      RECT  625.265 298.97 628.655 299.33 ;
      RECT  631.505 298.97 634.895 299.33 ;
      RECT  637.745 298.97 641.135 299.33 ;
      RECT  643.985 298.97 647.375 299.33 ;
      RECT  650.225 298.97 653.615 299.33 ;
      RECT  656.465 298.97 659.855 299.33 ;
      RECT  662.705 298.97 666.095 299.33 ;
      RECT  668.945 298.97 672.335 299.33 ;
      RECT  675.185 298.97 678.575 299.33 ;
      RECT  681.425 298.97 684.815 299.33 ;
      RECT  687.665 298.97 691.055 299.33 ;
      RECT  693.905 298.97 697.295 299.33 ;
      RECT  700.145 298.97 703.535 299.33 ;
      RECT  706.385 298.97 709.775 299.33 ;
      RECT  712.625 298.97 716.015 299.33 ;
      RECT  718.865 298.97 722.255 299.33 ;
      RECT  725.105 298.97 728.495 299.33 ;
      RECT  731.345 298.97 734.735 299.33 ;
      RECT  737.585 298.97 740.975 299.33 ;
      RECT  743.825 298.97 747.215 299.33 ;
      RECT  750.065 298.97 753.455 299.33 ;
      RECT  756.305 298.97 759.695 299.33 ;
      RECT  762.545 298.97 765.935 299.33 ;
      RECT  768.785 298.97 772.175 299.33 ;
      RECT  775.025 298.97 778.415 299.33 ;
      RECT  781.265 298.97 784.655 299.33 ;
      RECT  787.505 298.97 790.895 299.33 ;
      RECT  793.745 298.97 797.135 299.33 ;
      RECT  799.985 298.97 803.375 299.33 ;
      RECT  806.225 298.97 809.615 299.33 ;
      RECT  812.465 298.97 815.855 299.33 ;
      RECT  818.705 298.97 822.095 299.33 ;
      RECT  824.945 298.97 828.335 299.33 ;
      RECT  831.185 298.97 834.575 299.33 ;
      RECT  837.425 298.97 840.815 299.33 ;
      RECT  843.665 298.97 847.055 299.33 ;
      RECT  849.905 298.97 853.295 299.33 ;
      RECT  856.145 298.97 859.535 299.33 ;
      RECT  862.385 298.97 865.775 299.33 ;
      RECT  868.625 298.97 872.015 299.33 ;
      RECT  874.865 298.97 878.255 299.33 ;
      RECT  881.105 298.97 884.495 299.33 ;
      RECT  887.345 298.97 890.735 299.33 ;
      RECT  893.585 298.97 896.975 299.33 ;
      RECT  899.825 298.97 903.215 299.33 ;
      RECT  906.065 298.97 909.455 299.33 ;
      RECT  912.305 298.97 915.695 299.33 ;
      RECT  918.545 298.97 921.935 299.33 ;
      RECT  924.785 298.97 928.175 299.33 ;
      RECT  931.025 298.97 934.415 299.33 ;
      RECT  937.265 298.97 940.655 299.33 ;
      RECT  943.505 298.97 946.895 299.33 ;
      RECT  949.745 298.97 953.135 299.33 ;
      RECT  955.985 298.97 959.375 299.33 ;
      RECT  962.225 298.97 965.615 299.33 ;
      RECT  968.465 298.97 971.855 299.33 ;
      RECT  974.705 298.97 978.095 299.33 ;
      RECT  980.945 298.97 984.335 299.33 ;
      RECT  987.185 298.97 990.575 299.33 ;
      RECT  993.425 298.97 996.815 299.33 ;
      RECT  999.665 298.97 1003.055 299.33 ;
      RECT  1005.905 298.97 1009.295 299.33 ;
      RECT  1012.145 298.97 1015.535 299.33 ;
      RECT  1018.385 298.97 1021.775 299.33 ;
      RECT  1024.625 298.97 1028.015 299.33 ;
      RECT  1030.865 298.97 1034.255 299.33 ;
      RECT  1037.105 298.97 1040.495 299.33 ;
      RECT  1043.345 298.97 1046.735 299.33 ;
      RECT  1049.585 298.97 1052.975 299.33 ;
      RECT  1055.825 298.97 1059.215 299.33 ;
      RECT  1062.065 298.97 1065.455 299.33 ;
      RECT  1068.305 298.97 1071.695 299.33 ;
      RECT  1074.545 298.97 1077.935 299.33 ;
      RECT  1080.785 298.97 1084.175 299.33 ;
      RECT  1087.025 298.97 1090.415 299.33 ;
      RECT  1093.265 298.97 1096.655 299.33 ;
      RECT  1099.505 298.97 1102.895 299.33 ;
      RECT  1105.745 298.97 1109.135 299.33 ;
      RECT  1110.715 298.97 1183.785 299.33 ;
      RECT  1738.48 0.62 1752.58 0.98 ;
      RECT  1409.93 298.97 1752.58 299.33 ;
      RECT  2.34 0.62 247.7 0.98 ;
      RECT  2.34 298.97 234.48 299.33 ;
      RECT  1186.8 0.98 1749.1 2.88 ;
      RECT  1186.8 2.88 1749.1 297.07 ;
      RECT  1186.8 297.07 1749.1 298.97 ;
      RECT  1749.1 0.98 1752.04 2.88 ;
      RECT  1749.1 297.07 1752.04 298.97 ;
      RECT  1752.04 0.98 1752.58 2.88 ;
      RECT  1752.04 2.88 1752.58 297.07 ;
      RECT  1752.04 297.07 1752.58 298.97 ;
      RECT  2.34 0.98 2.88 2.88 ;
      RECT  2.34 2.88 2.88 297.07 ;
      RECT  2.34 297.07 2.88 298.97 ;
      RECT  2.88 0.98 5.82 2.88 ;
      RECT  2.88 297.07 5.82 298.97 ;
      RECT  5.82 0.98 238.145 2.88 ;
      RECT  5.82 2.88 238.145 297.07 ;
      RECT  5.82 297.07 238.145 298.97 ;
   END
END    l2_data_array
END    LIBRARY
